VERSION 5.8 ;
BUSBITCHARS "[]" ;
DIVIDERCHAR "/" ;
UNITS
    DATABASE MICRONS 1000 ;
END UNITS

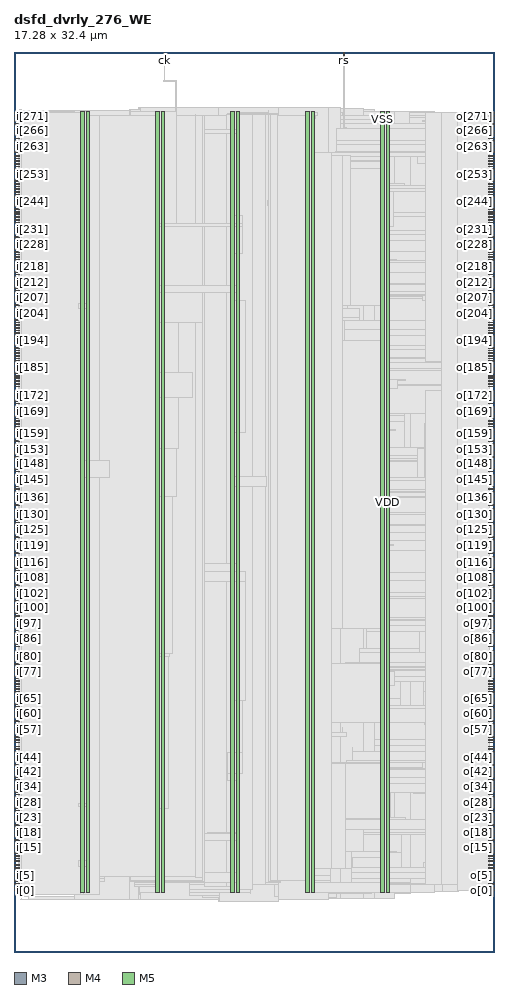
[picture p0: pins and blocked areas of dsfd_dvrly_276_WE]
MACRO dsfd_dvrly_276_WE
  FOREIGN dsfd_dvrly_276_WE 0 0 ;
  CLASS BLOCK ;
  SIZE 17.28 BY 32.4 ;
  PIN ck
    DIRECTION INPUT ;
    USE SIGNAL ;
    PORT
      LAYER M3 ;
        RECT  5.4 32.256 5.418 32.4 ;
    END
  END ck
  PIN i[0]
    DIRECTION INPUT ;
    USE SIGNAL ;
    PORT
      LAYER M4 ;
        RECT  0 2.208 0.192 2.232 ;
    END
  END i[0]
  PIN i[100]
    DIRECTION INPUT ;
    USE SIGNAL ;
    PORT
      LAYER M4 ;
        RECT  0 12.384 0.192 12.408 ;
    END
  END i[100]
  PIN i[101]
    DIRECTION INPUT ;
    USE SIGNAL ;
    PORT
      LAYER M4 ;
        RECT  0 12.48 0.192 12.504 ;
    END
  END i[101]
  PIN i[102]
    DIRECTION INPUT ;
    USE SIGNAL ;
    PORT
      LAYER M4 ;
        RECT  0 12.624 0.192 12.648 ;
    END
  END i[102]
  PIN i[103]
    DIRECTION INPUT ;
    USE SIGNAL ;
    PORT
      LAYER M4 ;
        RECT  0 12.72 0.192 12.744 ;
    END
  END i[103]
  PIN i[104]
    DIRECTION INPUT ;
    USE SIGNAL ;
    PORT
      LAYER M4 ;
        RECT  0 12.816 0.192 12.84 ;
    END
  END i[104]
  PIN i[105]
    DIRECTION INPUT ;
    USE SIGNAL ;
    PORT
      LAYER M4 ;
        RECT  0 12.912 0.192 12.936 ;
    END
  END i[105]
  PIN i[106]
    DIRECTION INPUT ;
    USE SIGNAL ;
    PORT
      LAYER M4 ;
        RECT  0 13.008 0.192 13.032 ;
    END
  END i[106]
  PIN i[107]
    DIRECTION INPUT ;
    USE SIGNAL ;
    PORT
      LAYER M4 ;
        RECT  0 13.104 0.192 13.128 ;
    END
  END i[107]
  PIN i[108]
    DIRECTION INPUT ;
    USE SIGNAL ;
    PORT
      LAYER M4 ;
        RECT  0 13.2 0.192 13.224 ;
    END
  END i[108]
  PIN i[109]
    DIRECTION INPUT ;
    USE SIGNAL ;
    PORT
      LAYER M4 ;
        RECT  0 13.296 0.192 13.32 ;
    END
  END i[109]
  PIN i[10]
    DIRECTION INPUT ;
    USE SIGNAL ;
    PORT
      LAYER M4 ;
        RECT  0 3.264 0.192 3.288 ;
    END
  END i[10]
  PIN i[110]
    DIRECTION INPUT ;
    USE SIGNAL ;
    PORT
      LAYER M4 ;
        RECT  0 13.392 0.192 13.416 ;
    END
  END i[110]
  PIN i[111]
    DIRECTION INPUT ;
    USE SIGNAL ;
    PORT
      LAYER M4 ;
        RECT  0 13.536 0.192 13.56 ;
    END
  END i[111]
  PIN i[112]
    DIRECTION INPUT ;
    USE SIGNAL ;
    PORT
      LAYER M4 ;
        RECT  0 13.632 0.192 13.656 ;
    END
  END i[112]
  PIN i[113]
    DIRECTION INPUT ;
    USE SIGNAL ;
    PORT
      LAYER M4 ;
        RECT  0 13.728 0.192 13.752 ;
    END
  END i[113]
  PIN i[114]
    DIRECTION INPUT ;
    USE SIGNAL ;
    PORT
      LAYER M4 ;
        RECT  0 13.824 0.192 13.848 ;
    END
  END i[114]
  PIN i[115]
    DIRECTION INPUT ;
    USE SIGNAL ;
    PORT
      LAYER M4 ;
        RECT  0 13.92 0.192 13.944 ;
    END
  END i[115]
  PIN i[116]
    DIRECTION INPUT ;
    USE SIGNAL ;
    PORT
      LAYER M4 ;
        RECT  0 14.016 0.192 14.04 ;
    END
  END i[116]
  PIN i[117]
    DIRECTION INPUT ;
    USE SIGNAL ;
    PORT
      LAYER M4 ;
        RECT  0 14.112 0.192 14.136 ;
    END
  END i[117]
  PIN i[118]
    DIRECTION INPUT ;
    USE SIGNAL ;
    PORT
      LAYER M4 ;
        RECT  0 14.208 0.192 14.232 ;
    END
  END i[118]
  PIN i[119]
    DIRECTION INPUT ;
    USE SIGNAL ;
    PORT
      LAYER M4 ;
        RECT  0 14.352 0.192 14.376 ;
    END
  END i[119]
  PIN i[11]
    DIRECTION INPUT ;
    USE SIGNAL ;
    PORT
      LAYER M4 ;
        RECT  0 3.36 0.192 3.384 ;
    END
  END i[11]
  PIN i[120]
    DIRECTION INPUT ;
    USE SIGNAL ;
    PORT
      LAYER M4 ;
        RECT  0 14.448 0.192 14.472 ;
    END
  END i[120]
  PIN i[121]
    DIRECTION INPUT ;
    USE SIGNAL ;
    PORT
      LAYER M4 ;
        RECT  0 14.544 0.192 14.568 ;
    END
  END i[121]
  PIN i[122]
    DIRECTION INPUT ;
    USE SIGNAL ;
    PORT
      LAYER M4 ;
        RECT  0 14.64 0.192 14.664 ;
    END
  END i[122]
  PIN i[123]
    DIRECTION INPUT ;
    USE SIGNAL ;
    PORT
      LAYER M4 ;
        RECT  0 14.736 0.192 14.76 ;
    END
  END i[123]
  PIN i[124]
    DIRECTION INPUT ;
    USE SIGNAL ;
    PORT
      LAYER M4 ;
        RECT  0 14.832 0.192 14.856 ;
    END
  END i[124]
  PIN i[125]
    DIRECTION INPUT ;
    USE SIGNAL ;
    PORT
      LAYER M4 ;
        RECT  0 14.928 0.192 14.952 ;
    END
  END i[125]
  PIN i[126]
    DIRECTION INPUT ;
    USE SIGNAL ;
    PORT
      LAYER M4 ;
        RECT  0 15.024 0.192 15.048 ;
    END
  END i[126]
  PIN i[127]
    DIRECTION INPUT ;
    USE SIGNAL ;
    PORT
      LAYER M4 ;
        RECT  0 15.12 0.192 15.144 ;
    END
  END i[127]
  PIN i[128]
    DIRECTION INPUT ;
    USE SIGNAL ;
    PORT
      LAYER M4 ;
        RECT  0 15.264 0.192 15.288 ;
    END
  END i[128]
  PIN i[129]
    DIRECTION INPUT ;
    USE SIGNAL ;
    PORT
      LAYER M4 ;
        RECT  0 15.36 0.192 15.384 ;
    END
  END i[129]
  PIN i[12]
    DIRECTION INPUT ;
    USE SIGNAL ;
    PORT
      LAYER M4 ;
        RECT  0 3.456 0.192 3.48 ;
    END
  END i[12]
  PIN i[130]
    DIRECTION INPUT ;
    USE SIGNAL ;
    PORT
      LAYER M4 ;
        RECT  0 15.456 0.192 15.48 ;
    END
  END i[130]
  PIN i[131]
    DIRECTION INPUT ;
    USE SIGNAL ;
    PORT
      LAYER M4 ;
        RECT  0 15.552 0.192 15.576 ;
    END
  END i[131]
  PIN i[132]
    DIRECTION INPUT ;
    USE SIGNAL ;
    PORT
      LAYER M4 ;
        RECT  0 15.648 0.192 15.672 ;
    END
  END i[132]
  PIN i[133]
    DIRECTION INPUT ;
    USE SIGNAL ;
    PORT
      LAYER M4 ;
        RECT  0 15.744 0.192 15.768 ;
    END
  END i[133]
  PIN i[134]
    DIRECTION INPUT ;
    USE SIGNAL ;
    PORT
      LAYER M4 ;
        RECT  0 15.84 0.192 15.864 ;
    END
  END i[134]
  PIN i[135]
    DIRECTION INPUT ;
    USE SIGNAL ;
    PORT
      LAYER M4 ;
        RECT  0 15.936 0.192 15.96 ;
    END
  END i[135]
  PIN i[136]
    DIRECTION INPUT ;
    USE SIGNAL ;
    PORT
      LAYER M4 ;
        RECT  0 16.08 0.192 16.104 ;
    END
  END i[136]
  PIN i[137]
    DIRECTION INPUT ;
    USE SIGNAL ;
    PORT
      LAYER M4 ;
        RECT  0 16.176 0.192 16.2 ;
    END
  END i[137]
  PIN i[138]
    DIRECTION INPUT ;
    USE SIGNAL ;
    PORT
      LAYER M4 ;
        RECT  0 16.272 0.192 16.296 ;
    END
  END i[138]
  PIN i[139]
    DIRECTION INPUT ;
    USE SIGNAL ;
    PORT
      LAYER M4 ;
        RECT  0 16.368 0.192 16.392 ;
    END
  END i[139]
  PIN i[13]
    DIRECTION INPUT ;
    USE SIGNAL ;
    PORT
      LAYER M4 ;
        RECT  0 3.552 0.192 3.576 ;
    END
  END i[13]
  PIN i[140]
    DIRECTION INPUT ;
    USE SIGNAL ;
    PORT
      LAYER M4 ;
        RECT  0 16.464 0.192 16.488 ;
    END
  END i[140]
  PIN i[141]
    DIRECTION INPUT ;
    USE SIGNAL ;
    PORT
      LAYER M4 ;
        RECT  0 16.56 0.192 16.584 ;
    END
  END i[141]
  PIN i[142]
    DIRECTION INPUT ;
    USE SIGNAL ;
    PORT
      LAYER M4 ;
        RECT  0 16.656 0.192 16.68 ;
    END
  END i[142]
  PIN i[143]
    DIRECTION INPUT ;
    USE SIGNAL ;
    PORT
      LAYER M4 ;
        RECT  0 16.752 0.192 16.776 ;
    END
  END i[143]
  PIN i[144]
    DIRECTION INPUT ;
    USE SIGNAL ;
    PORT
      LAYER M4 ;
        RECT  0 16.896 0.192 16.92 ;
    END
  END i[144]
  PIN i[145]
    DIRECTION INPUT ;
    USE SIGNAL ;
    PORT
      LAYER M4 ;
        RECT  0 16.992 0.192 17.016 ;
    END
  END i[145]
  PIN i[146]
    DIRECTION INPUT ;
    USE SIGNAL ;
    PORT
      LAYER M4 ;
        RECT  0 17.088 0.192 17.112 ;
    END
  END i[146]
  PIN i[147]
    DIRECTION INPUT ;
    USE SIGNAL ;
    PORT
      LAYER M4 ;
        RECT  0 17.184 0.192 17.208 ;
    END
  END i[147]
  PIN i[148]
    DIRECTION INPUT ;
    USE SIGNAL ;
    PORT
      LAYER M4 ;
        RECT  0 17.28 0.192 17.304 ;
    END
  END i[148]
  PIN i[149]
    DIRECTION INPUT ;
    USE SIGNAL ;
    PORT
      LAYER M4 ;
        RECT  0 17.376 0.192 17.4 ;
    END
  END i[149]
  PIN i[14]
    DIRECTION INPUT ;
    USE SIGNAL ;
    PORT
      LAYER M4 ;
        RECT  0 3.648 0.192 3.672 ;
    END
  END i[14]
  PIN i[150]
    DIRECTION INPUT ;
    USE SIGNAL ;
    PORT
      LAYER M4 ;
        RECT  0 17.472 0.192 17.496 ;
    END
  END i[150]
  PIN i[151]
    DIRECTION INPUT ;
    USE SIGNAL ;
    PORT
      LAYER M4 ;
        RECT  0 17.568 0.192 17.592 ;
    END
  END i[151]
  PIN i[152]
    DIRECTION INPUT ;
    USE SIGNAL ;
    PORT
      LAYER M4 ;
        RECT  0 17.664 0.192 17.688 ;
    END
  END i[152]
  PIN i[153]
    DIRECTION INPUT ;
    USE SIGNAL ;
    PORT
      LAYER M4 ;
        RECT  0 17.808 0.192 17.832 ;
    END
  END i[153]
  PIN i[154]
    DIRECTION INPUT ;
    USE SIGNAL ;
    PORT
      LAYER M4 ;
        RECT  0 17.904 0.192 17.928 ;
    END
  END i[154]
  PIN i[155]
    DIRECTION INPUT ;
    USE SIGNAL ;
    PORT
      LAYER M4 ;
        RECT  0 18 0.192 18.024 ;
    END
  END i[155]
  PIN i[156]
    DIRECTION INPUT ;
    USE SIGNAL ;
    PORT
      LAYER M4 ;
        RECT  0 18.096 0.192 18.12 ;
    END
  END i[156]
  PIN i[157]
    DIRECTION INPUT ;
    USE SIGNAL ;
    PORT
      LAYER M4 ;
        RECT  0 18.192 0.192 18.216 ;
    END
  END i[157]
  PIN i[158]
    DIRECTION INPUT ;
    USE SIGNAL ;
    PORT
      LAYER M4 ;
        RECT  0 18.288 0.192 18.312 ;
    END
  END i[158]
  PIN i[159]
    DIRECTION INPUT ;
    USE SIGNAL ;
    PORT
      LAYER M4 ;
        RECT  0 18.384 0.192 18.408 ;
    END
  END i[159]
  PIN i[15]
    DIRECTION INPUT ;
    USE SIGNAL ;
    PORT
      LAYER M4 ;
        RECT  0 3.744 0.192 3.768 ;
    END
  END i[15]
  PIN i[160]
    DIRECTION INPUT ;
    USE SIGNAL ;
    PORT
      LAYER M4 ;
        RECT  0 18.48 0.192 18.504 ;
    END
  END i[160]
  PIN i[161]
    DIRECTION INPUT ;
    USE SIGNAL ;
    PORT
      LAYER M4 ;
        RECT  0 18.624 0.192 18.648 ;
    END
  END i[161]
  PIN i[162]
    DIRECTION INPUT ;
    USE SIGNAL ;
    PORT
      LAYER M4 ;
        RECT  0 18.72 0.192 18.744 ;
    END
  END i[162]
  PIN i[163]
    DIRECTION INPUT ;
    USE SIGNAL ;
    PORT
      LAYER M4 ;
        RECT  0 18.816 0.192 18.84 ;
    END
  END i[163]
  PIN i[164]
    DIRECTION INPUT ;
    USE SIGNAL ;
    PORT
      LAYER M4 ;
        RECT  0 18.912 0.192 18.936 ;
    END
  END i[164]
  PIN i[165]
    DIRECTION INPUT ;
    USE SIGNAL ;
    PORT
      LAYER M4 ;
        RECT  0 19.008 0.192 19.032 ;
    END
  END i[165]
  PIN i[166]
    DIRECTION INPUT ;
    USE SIGNAL ;
    PORT
      LAYER M4 ;
        RECT  0 19.104 0.192 19.128 ;
    END
  END i[166]
  PIN i[167]
    DIRECTION INPUT ;
    USE SIGNAL ;
    PORT
      LAYER M4 ;
        RECT  0 19.2 0.192 19.224 ;
    END
  END i[167]
  PIN i[168]
    DIRECTION INPUT ;
    USE SIGNAL ;
    PORT
      LAYER M4 ;
        RECT  0 19.296 0.192 19.32 ;
    END
  END i[168]
  PIN i[169]
    DIRECTION INPUT ;
    USE SIGNAL ;
    PORT
      LAYER M4 ;
        RECT  0 19.44 0.192 19.464 ;
    END
  END i[169]
  PIN i[16]
    DIRECTION INPUT ;
    USE SIGNAL ;
    PORT
      LAYER M4 ;
        RECT  0 3.84 0.192 3.864 ;
    END
  END i[16]
  PIN i[170]
    DIRECTION INPUT ;
    USE SIGNAL ;
    PORT
      LAYER M4 ;
        RECT  0 19.536 0.192 19.56 ;
    END
  END i[170]
  PIN i[171]
    DIRECTION INPUT ;
    USE SIGNAL ;
    PORT
      LAYER M4 ;
        RECT  0 19.632 0.192 19.656 ;
    END
  END i[171]
  PIN i[172]
    DIRECTION INPUT ;
    USE SIGNAL ;
    PORT
      LAYER M4 ;
        RECT  0 19.728 0.192 19.752 ;
    END
  END i[172]
  PIN i[173]
    DIRECTION INPUT ;
    USE SIGNAL ;
    PORT
      LAYER M4 ;
        RECT  0 19.824 0.192 19.848 ;
    END
  END i[173]
  PIN i[174]
    DIRECTION INPUT ;
    USE SIGNAL ;
    PORT
      LAYER M4 ;
        RECT  0 19.92 0.192 19.944 ;
    END
  END i[174]
  PIN i[175]
    DIRECTION INPUT ;
    USE SIGNAL ;
    PORT
      LAYER M4 ;
        RECT  0 20.016 0.192 20.04 ;
    END
  END i[175]
  PIN i[176]
    DIRECTION INPUT ;
    USE SIGNAL ;
    PORT
      LAYER M4 ;
        RECT  0 20.112 0.192 20.136 ;
    END
  END i[176]
  PIN i[177]
    DIRECTION INPUT ;
    USE SIGNAL ;
    PORT
      LAYER M4 ;
        RECT  0 20.208 0.192 20.232 ;
    END
  END i[177]
  PIN i[178]
    DIRECTION INPUT ;
    USE SIGNAL ;
    PORT
      LAYER M4 ;
        RECT  0 20.352 0.192 20.376 ;
    END
  END i[178]
  PIN i[179]
    DIRECTION INPUT ;
    USE SIGNAL ;
    PORT
      LAYER M4 ;
        RECT  0 20.448 0.192 20.472 ;
    END
  END i[179]
  PIN i[17]
    DIRECTION INPUT ;
    USE SIGNAL ;
    PORT
      LAYER M4 ;
        RECT  0 3.936 0.192 3.96 ;
    END
  END i[17]
  PIN i[180]
    DIRECTION INPUT ;
    USE SIGNAL ;
    PORT
      LAYER M4 ;
        RECT  0 20.544 0.192 20.568 ;
    END
  END i[180]
  PIN i[181]
    DIRECTION INPUT ;
    USE SIGNAL ;
    PORT
      LAYER M4 ;
        RECT  0 20.64 0.192 20.664 ;
    END
  END i[181]
  PIN i[182]
    DIRECTION INPUT ;
    USE SIGNAL ;
    PORT
      LAYER M4 ;
        RECT  0 20.736 0.192 20.76 ;
    END
  END i[182]
  PIN i[183]
    DIRECTION INPUT ;
    USE SIGNAL ;
    PORT
      LAYER M4 ;
        RECT  0 20.832 0.192 20.856 ;
    END
  END i[183]
  PIN i[184]
    DIRECTION INPUT ;
    USE SIGNAL ;
    PORT
      LAYER M4 ;
        RECT  0 20.928 0.192 20.952 ;
    END
  END i[184]
  PIN i[185]
    DIRECTION INPUT ;
    USE SIGNAL ;
    PORT
      LAYER M4 ;
        RECT  0 21.024 0.192 21.048 ;
    END
  END i[185]
  PIN i[186]
    DIRECTION INPUT ;
    USE SIGNAL ;
    PORT
      LAYER M4 ;
        RECT  0 21.168 0.192 21.192 ;
    END
  END i[186]
  PIN i[187]
    DIRECTION INPUT ;
    USE SIGNAL ;
    PORT
      LAYER M4 ;
        RECT  0 21.264 0.192 21.288 ;
    END
  END i[187]
  PIN i[188]
    DIRECTION INPUT ;
    USE SIGNAL ;
    PORT
      LAYER M4 ;
        RECT  0 21.36 0.192 21.384 ;
    END
  END i[188]
  PIN i[189]
    DIRECTION INPUT ;
    USE SIGNAL ;
    PORT
      LAYER M4 ;
        RECT  0 21.456 0.192 21.48 ;
    END
  END i[189]
  PIN i[18]
    DIRECTION INPUT ;
    USE SIGNAL ;
    PORT
      LAYER M4 ;
        RECT  0 4.032 0.192 4.056 ;
    END
  END i[18]
  PIN i[190]
    DIRECTION INPUT ;
    USE SIGNAL ;
    PORT
      LAYER M4 ;
        RECT  0 21.552 0.192 21.576 ;
    END
  END i[190]
  PIN i[191]
    DIRECTION INPUT ;
    USE SIGNAL ;
    PORT
      LAYER M4 ;
        RECT  0 21.648 0.192 21.672 ;
    END
  END i[191]
  PIN i[192]
    DIRECTION INPUT ;
    USE SIGNAL ;
    PORT
      LAYER M4 ;
        RECT  0 21.744 0.192 21.768 ;
    END
  END i[192]
  PIN i[193]
    DIRECTION INPUT ;
    USE SIGNAL ;
    PORT
      LAYER M4 ;
        RECT  0 21.84 0.192 21.864 ;
    END
  END i[193]
  PIN i[194]
    DIRECTION INPUT ;
    USE SIGNAL ;
    PORT
      LAYER M4 ;
        RECT  0 21.984 0.192 22.008 ;
    END
  END i[194]
  PIN i[195]
    DIRECTION INPUT ;
    USE SIGNAL ;
    PORT
      LAYER M4 ;
        RECT  0 22.08 0.192 22.104 ;
    END
  END i[195]
  PIN i[196]
    DIRECTION INPUT ;
    USE SIGNAL ;
    PORT
      LAYER M4 ;
        RECT  0 22.176 0.192 22.2 ;
    END
  END i[196]
  PIN i[197]
    DIRECTION INPUT ;
    USE SIGNAL ;
    PORT
      LAYER M4 ;
        RECT  0 22.272 0.192 22.296 ;
    END
  END i[197]
  PIN i[198]
    DIRECTION INPUT ;
    USE SIGNAL ;
    PORT
      LAYER M4 ;
        RECT  0 22.368 0.192 22.392 ;
    END
  END i[198]
  PIN i[199]
    DIRECTION INPUT ;
    USE SIGNAL ;
    PORT
      LAYER M4 ;
        RECT  0 22.464 0.192 22.488 ;
    END
  END i[199]
  PIN i[19]
    DIRECTION INPUT ;
    USE SIGNAL ;
    PORT
      LAYER M4 ;
        RECT  0 4.176 0.192 4.2 ;
    END
  END i[19]
  PIN i[1]
    DIRECTION INPUT ;
    USE SIGNAL ;
    PORT
      LAYER M4 ;
        RECT  0 2.304 0.192 2.328 ;
    END
  END i[1]
  PIN i[200]
    DIRECTION INPUT ;
    USE SIGNAL ;
    PORT
      LAYER M4 ;
        RECT  0 22.56 0.192 22.584 ;
    END
  END i[200]
  PIN i[201]
    DIRECTION INPUT ;
    USE SIGNAL ;
    PORT
      LAYER M4 ;
        RECT  0 22.656 0.192 22.68 ;
    END
  END i[201]
  PIN i[202]
    DIRECTION INPUT ;
    USE SIGNAL ;
    PORT
      LAYER M4 ;
        RECT  0 22.752 0.192 22.776 ;
    END
  END i[202]
  PIN i[203]
    DIRECTION INPUT ;
    USE SIGNAL ;
    PORT
      LAYER M4 ;
        RECT  0 22.896 0.192 22.92 ;
    END
  END i[203]
  PIN i[204]
    DIRECTION INPUT ;
    USE SIGNAL ;
    PORT
      LAYER M4 ;
        RECT  0 22.992 0.192 23.016 ;
    END
  END i[204]
  PIN i[205]
    DIRECTION INPUT ;
    USE SIGNAL ;
    PORT
      LAYER M4 ;
        RECT  0 23.088 0.192 23.112 ;
    END
  END i[205]
  PIN i[206]
    DIRECTION INPUT ;
    USE SIGNAL ;
    PORT
      LAYER M4 ;
        RECT  0 23.184 0.192 23.208 ;
    END
  END i[206]
  PIN i[207]
    DIRECTION INPUT ;
    USE SIGNAL ;
    PORT
      LAYER M4 ;
        RECT  0 23.28 0.192 23.304 ;
    END
  END i[207]
  PIN i[208]
    DIRECTION INPUT ;
    USE SIGNAL ;
    PORT
      LAYER M4 ;
        RECT  0 23.376 0.192 23.4 ;
    END
  END i[208]
  PIN i[209]
    DIRECTION INPUT ;
    USE SIGNAL ;
    PORT
      LAYER M4 ;
        RECT  0 23.472 0.192 23.496 ;
    END
  END i[209]
  PIN i[20]
    DIRECTION INPUT ;
    USE SIGNAL ;
    PORT
      LAYER M4 ;
        RECT  0 4.272 0.192 4.296 ;
    END
  END i[20]
  PIN i[210]
    DIRECTION INPUT ;
    USE SIGNAL ;
    PORT
      LAYER M4 ;
        RECT  0 23.568 0.192 23.592 ;
    END
  END i[210]
  PIN i[211]
    DIRECTION INPUT ;
    USE SIGNAL ;
    PORT
      LAYER M4 ;
        RECT  0 23.712 0.192 23.736 ;
    END
  END i[211]
  PIN i[212]
    DIRECTION INPUT ;
    USE SIGNAL ;
    PORT
      LAYER M4 ;
        RECT  0 23.808 0.192 23.832 ;
    END
  END i[212]
  PIN i[213]
    DIRECTION INPUT ;
    USE SIGNAL ;
    PORT
      LAYER M4 ;
        RECT  0 23.904 0.192 23.928 ;
    END
  END i[213]
  PIN i[214]
    DIRECTION INPUT ;
    USE SIGNAL ;
    PORT
      LAYER M4 ;
        RECT  0 24 0.192 24.024 ;
    END
  END i[214]
  PIN i[215]
    DIRECTION INPUT ;
    USE SIGNAL ;
    PORT
      LAYER M4 ;
        RECT  0 24.096 0.192 24.12 ;
    END
  END i[215]
  PIN i[216]
    DIRECTION INPUT ;
    USE SIGNAL ;
    PORT
      LAYER M4 ;
        RECT  0 24.192 0.192 24.216 ;
    END
  END i[216]
  PIN i[217]
    DIRECTION INPUT ;
    USE SIGNAL ;
    PORT
      LAYER M4 ;
        RECT  0 24.288 0.192 24.312 ;
    END
  END i[217]
  PIN i[218]
    DIRECTION INPUT ;
    USE SIGNAL ;
    PORT
      LAYER M4 ;
        RECT  0 24.384 0.192 24.408 ;
    END
  END i[218]
  PIN i[219]
    DIRECTION INPUT ;
    USE SIGNAL ;
    PORT
      LAYER M4 ;
        RECT  0 24.48 0.192 24.504 ;
    END
  END i[219]
  PIN i[21]
    DIRECTION INPUT ;
    USE SIGNAL ;
    PORT
      LAYER M4 ;
        RECT  0 4.368 0.192 4.392 ;
    END
  END i[21]
  PIN i[220]
    DIRECTION INPUT ;
    USE SIGNAL ;
    PORT
      LAYER M4 ;
        RECT  0 24.624 0.192 24.648 ;
    END
  END i[220]
  PIN i[221]
    DIRECTION INPUT ;
    USE SIGNAL ;
    PORT
      LAYER M4 ;
        RECT  0 24.72 0.192 24.744 ;
    END
  END i[221]
  PIN i[222]
    DIRECTION INPUT ;
    USE SIGNAL ;
    PORT
      LAYER M4 ;
        RECT  0 24.816 0.192 24.84 ;
    END
  END i[222]
  PIN i[223]
    DIRECTION INPUT ;
    USE SIGNAL ;
    PORT
      LAYER M4 ;
        RECT  0 24.912 0.192 24.936 ;
    END
  END i[223]
  PIN i[224]
    DIRECTION INPUT ;
    USE SIGNAL ;
    PORT
      LAYER M4 ;
        RECT  0 25.008 0.192 25.032 ;
    END
  END i[224]
  PIN i[225]
    DIRECTION INPUT ;
    USE SIGNAL ;
    PORT
      LAYER M4 ;
        RECT  0 25.104 0.192 25.128 ;
    END
  END i[225]
  PIN i[226]
    DIRECTION INPUT ;
    USE SIGNAL ;
    PORT
      LAYER M4 ;
        RECT  0 25.2 0.192 25.224 ;
    END
  END i[226]
  PIN i[227]
    DIRECTION INPUT ;
    USE SIGNAL ;
    PORT
      LAYER M4 ;
        RECT  0 25.296 0.192 25.32 ;
    END
  END i[227]
  PIN i[228]
    DIRECTION INPUT ;
    USE SIGNAL ;
    PORT
      LAYER M4 ;
        RECT  0 25.44 0.192 25.464 ;
    END
  END i[228]
  PIN i[229]
    DIRECTION INPUT ;
    USE SIGNAL ;
    PORT
      LAYER M4 ;
        RECT  0 25.536 0.192 25.56 ;
    END
  END i[229]
  PIN i[22]
    DIRECTION INPUT ;
    USE SIGNAL ;
    PORT
      LAYER M4 ;
        RECT  0 4.464 0.192 4.488 ;
    END
  END i[22]
  PIN i[230]
    DIRECTION INPUT ;
    USE SIGNAL ;
    PORT
      LAYER M4 ;
        RECT  0 25.632 0.192 25.656 ;
    END
  END i[230]
  PIN i[231]
    DIRECTION INPUT ;
    USE SIGNAL ;
    PORT
      LAYER M4 ;
        RECT  0 25.728 0.192 25.752 ;
    END
  END i[231]
  PIN i[232]
    DIRECTION INPUT ;
    USE SIGNAL ;
    PORT
      LAYER M4 ;
        RECT  0 25.824 0.192 25.848 ;
    END
  END i[232]
  PIN i[233]
    DIRECTION INPUT ;
    USE SIGNAL ;
    PORT
      LAYER M4 ;
        RECT  0 25.92 0.192 25.944 ;
    END
  END i[233]
  PIN i[234]
    DIRECTION INPUT ;
    USE SIGNAL ;
    PORT
      LAYER M4 ;
        RECT  0 26.016 0.192 26.04 ;
    END
  END i[234]
  PIN i[235]
    DIRECTION INPUT ;
    USE SIGNAL ;
    PORT
      LAYER M4 ;
        RECT  0 26.112 0.192 26.136 ;
    END
  END i[235]
  PIN i[236]
    DIRECTION INPUT ;
    USE SIGNAL ;
    PORT
      LAYER M4 ;
        RECT  0 26.256 0.192 26.28 ;
    END
  END i[236]
  PIN i[237]
    DIRECTION INPUT ;
    USE SIGNAL ;
    PORT
      LAYER M4 ;
        RECT  0 26.352 0.192 26.376 ;
    END
  END i[237]
  PIN i[238]
    DIRECTION INPUT ;
    USE SIGNAL ;
    PORT
      LAYER M4 ;
        RECT  0 26.448 0.192 26.472 ;
    END
  END i[238]
  PIN i[239]
    DIRECTION INPUT ;
    USE SIGNAL ;
    PORT
      LAYER M4 ;
        RECT  0 26.544 0.192 26.568 ;
    END
  END i[239]
  PIN i[23]
    DIRECTION INPUT ;
    USE SIGNAL ;
    PORT
      LAYER M4 ;
        RECT  0 4.56 0.192 4.584 ;
    END
  END i[23]
  PIN i[240]
    DIRECTION INPUT ;
    USE SIGNAL ;
    PORT
      LAYER M4 ;
        RECT  0 26.64 0.192 26.664 ;
    END
  END i[240]
  PIN i[241]
    DIRECTION INPUT ;
    USE SIGNAL ;
    PORT
      LAYER M4 ;
        RECT  0 26.736 0.192 26.76 ;
    END
  END i[241]
  PIN i[242]
    DIRECTION INPUT ;
    USE SIGNAL ;
    PORT
      LAYER M4 ;
        RECT  0 26.832 0.192 26.856 ;
    END
  END i[242]
  PIN i[243]
    DIRECTION INPUT ;
    USE SIGNAL ;
    PORT
      LAYER M4 ;
        RECT  0 26.928 0.192 26.952 ;
    END
  END i[243]
  PIN i[244]
    DIRECTION INPUT ;
    USE SIGNAL ;
    PORT
      LAYER M4 ;
        RECT  0 27.024 0.192 27.048 ;
    END
  END i[244]
  PIN i[245]
    DIRECTION INPUT ;
    USE SIGNAL ;
    PORT
      LAYER M4 ;
        RECT  0 27.168 0.192 27.192 ;
    END
  END i[245]
  PIN i[246]
    DIRECTION INPUT ;
    USE SIGNAL ;
    PORT
      LAYER M4 ;
        RECT  0 27.264 0.192 27.288 ;
    END
  END i[246]
  PIN i[247]
    DIRECTION INPUT ;
    USE SIGNAL ;
    PORT
      LAYER M4 ;
        RECT  0 27.36 0.192 27.384 ;
    END
  END i[247]
  PIN i[248]
    DIRECTION INPUT ;
    USE SIGNAL ;
    PORT
      LAYER M4 ;
        RECT  0 27.456 0.192 27.48 ;
    END
  END i[248]
  PIN i[249]
    DIRECTION INPUT ;
    USE SIGNAL ;
    PORT
      LAYER M4 ;
        RECT  0 27.552 0.192 27.576 ;
    END
  END i[249]
  PIN i[24]
    DIRECTION INPUT ;
    USE SIGNAL ;
    PORT
      LAYER M4 ;
        RECT  0 4.656 0.192 4.68 ;
    END
  END i[24]
  PIN i[250]
    DIRECTION INPUT ;
    USE SIGNAL ;
    PORT
      LAYER M4 ;
        RECT  0 27.648 0.192 27.672 ;
    END
  END i[250]
  PIN i[251]
    DIRECTION INPUT ;
    USE SIGNAL ;
    PORT
      LAYER M4 ;
        RECT  0 27.744 0.192 27.768 ;
    END
  END i[251]
  PIN i[252]
    DIRECTION INPUT ;
    USE SIGNAL ;
    PORT
      LAYER M4 ;
        RECT  0 27.84 0.192 27.864 ;
    END
  END i[252]
  PIN i[253]
    DIRECTION INPUT ;
    USE SIGNAL ;
    PORT
      LAYER M4 ;
        RECT  0 27.984 0.192 28.008 ;
    END
  END i[253]
  PIN i[254]
    DIRECTION INPUT ;
    USE SIGNAL ;
    PORT
      LAYER M4 ;
        RECT  0 28.08 0.192 28.104 ;
    END
  END i[254]
  PIN i[255]
    DIRECTION INPUT ;
    USE SIGNAL ;
    PORT
      LAYER M4 ;
        RECT  0 28.176 0.192 28.2 ;
    END
  END i[255]
  PIN i[256]
    DIRECTION INPUT ;
    USE SIGNAL ;
    PORT
      LAYER M4 ;
        RECT  0 28.272 0.192 28.296 ;
    END
  END i[256]
  PIN i[257]
    DIRECTION INPUT ;
    USE SIGNAL ;
    PORT
      LAYER M4 ;
        RECT  0 28.368 0.192 28.392 ;
    END
  END i[257]
  PIN i[258]
    DIRECTION INPUT ;
    USE SIGNAL ;
    PORT
      LAYER M4 ;
        RECT  0 28.464 0.192 28.488 ;
    END
  END i[258]
  PIN i[259]
    DIRECTION INPUT ;
    USE SIGNAL ;
    PORT
      LAYER M4 ;
        RECT  0 28.56 0.192 28.584 ;
    END
  END i[259]
  PIN i[25]
    DIRECTION INPUT ;
    USE SIGNAL ;
    PORT
      LAYER M4 ;
        RECT  0 4.752 0.192 4.776 ;
    END
  END i[25]
  PIN i[260]
    DIRECTION INPUT ;
    USE SIGNAL ;
    PORT
      LAYER M4 ;
        RECT  0 28.656 0.192 28.68 ;
    END
  END i[260]
  PIN i[261]
    DIRECTION INPUT ;
    USE SIGNAL ;
    PORT
      LAYER M4 ;
        RECT  0 28.8 0.192 28.824 ;
    END
  END i[261]
  PIN i[262]
    DIRECTION INPUT ;
    USE SIGNAL ;
    PORT
      LAYER M4 ;
        RECT  0 28.896 0.192 28.92 ;
    END
  END i[262]
  PIN i[263]
    DIRECTION INPUT ;
    USE SIGNAL ;
    PORT
      LAYER M4 ;
        RECT  0 28.992 0.192 29.016 ;
    END
  END i[263]
  PIN i[264]
    DIRECTION INPUT ;
    USE SIGNAL ;
    PORT
      LAYER M4 ;
        RECT  0 29.088 0.192 29.112 ;
    END
  END i[264]
  PIN i[265]
    DIRECTION INPUT ;
    USE SIGNAL ;
    PORT
      LAYER M4 ;
        RECT  0 29.184 0.192 29.208 ;
    END
  END i[265]
  PIN i[266]
    DIRECTION INPUT ;
    USE SIGNAL ;
    PORT
      LAYER M4 ;
        RECT  0 29.28 0.192 29.304 ;
    END
  END i[266]
  PIN i[267]
    DIRECTION INPUT ;
    USE SIGNAL ;
    PORT
      LAYER M4 ;
        RECT  0 29.376 0.192 29.4 ;
    END
  END i[267]
  PIN i[268]
    DIRECTION INPUT ;
    USE SIGNAL ;
    PORT
      LAYER M4 ;
        RECT  0 29.472 0.192 29.496 ;
    END
  END i[268]
  PIN i[269]
    DIRECTION INPUT ;
    USE SIGNAL ;
    PORT
      LAYER M4 ;
        RECT  0 29.568 0.192 29.592 ;
    END
  END i[269]
  PIN i[26]
    DIRECTION INPUT ;
    USE SIGNAL ;
    PORT
      LAYER M4 ;
        RECT  0 4.848 0.192 4.872 ;
    END
  END i[26]
  PIN i[270]
    DIRECTION INPUT ;
    USE SIGNAL ;
    PORT
      LAYER M4 ;
        RECT  0 29.712 0.192 29.736 ;
    END
  END i[270]
  PIN i[271]
    DIRECTION INPUT ;
    USE SIGNAL ;
    PORT
      LAYER M4 ;
        RECT  0 29.808 0.192 29.832 ;
    END
  END i[271]
  PIN i[272]
    DIRECTION INPUT ;
    USE SIGNAL ;
    PORT
      LAYER M4 ;
        RECT  0 29.904 0.192 29.928 ;
    END
  END i[272]
  PIN i[273]
    DIRECTION INPUT ;
    USE SIGNAL ;
    PORT
      LAYER M4 ;
        RECT  0 30 0.192 30.024 ;
    END
  END i[273]
  PIN i[274]
    DIRECTION INPUT ;
    USE SIGNAL ;
    PORT
      LAYER M4 ;
        RECT  0 30.096 0.192 30.12 ;
    END
  END i[274]
  PIN i[275]
    DIRECTION INPUT ;
    USE SIGNAL ;
    PORT
      LAYER M4 ;
        RECT  0 30.192 0.192 30.216 ;
    END
  END i[275]
  PIN i[27]
    DIRECTION INPUT ;
    USE SIGNAL ;
    PORT
      LAYER M4 ;
        RECT  0 4.992 0.192 5.016 ;
    END
  END i[27]
  PIN i[28]
    DIRECTION INPUT ;
    USE SIGNAL ;
    PORT
      LAYER M4 ;
        RECT  0 5.088 0.192 5.112 ;
    END
  END i[28]
  PIN i[29]
    DIRECTION INPUT ;
    USE SIGNAL ;
    PORT
      LAYER M4 ;
        RECT  0 5.184 0.192 5.208 ;
    END
  END i[29]
  PIN i[2]
    DIRECTION INPUT ;
    USE SIGNAL ;
    PORT
      LAYER M4 ;
        RECT  0 2.448 0.192 2.472 ;
    END
  END i[2]
  PIN i[30]
    DIRECTION INPUT ;
    USE SIGNAL ;
    PORT
      LAYER M4 ;
        RECT  0 5.28 0.192 5.304 ;
    END
  END i[30]
  PIN i[31]
    DIRECTION INPUT ;
    USE SIGNAL ;
    PORT
      LAYER M4 ;
        RECT  0 5.376 0.192 5.4 ;
    END
  END i[31]
  PIN i[32]
    DIRECTION INPUT ;
    USE SIGNAL ;
    PORT
      LAYER M4 ;
        RECT  0 5.472 0.192 5.496 ;
    END
  END i[32]
  PIN i[33]
    DIRECTION INPUT ;
    USE SIGNAL ;
    PORT
      LAYER M4 ;
        RECT  0 5.568 0.192 5.592 ;
    END
  END i[33]
  PIN i[34]
    DIRECTION INPUT ;
    USE SIGNAL ;
    PORT
      LAYER M4 ;
        RECT  0 5.664 0.192 5.688 ;
    END
  END i[34]
  PIN i[35]
    DIRECTION INPUT ;
    USE SIGNAL ;
    PORT
      LAYER M4 ;
        RECT  0 5.76 0.192 5.784 ;
    END
  END i[35]
  PIN i[36]
    DIRECTION INPUT ;
    USE SIGNAL ;
    PORT
      LAYER M4 ;
        RECT  0 5.904 0.192 5.928 ;
    END
  END i[36]
  PIN i[37]
    DIRECTION INPUT ;
    USE SIGNAL ;
    PORT
      LAYER M4 ;
        RECT  0 6 0.192 6.024 ;
    END
  END i[37]
  PIN i[38]
    DIRECTION INPUT ;
    USE SIGNAL ;
    PORT
      LAYER M4 ;
        RECT  0 6.096 0.192 6.12 ;
    END
  END i[38]
  PIN i[39]
    DIRECTION INPUT ;
    USE SIGNAL ;
    PORT
      LAYER M4 ;
        RECT  0 6.192 0.192 6.216 ;
    END
  END i[39]
  PIN i[3]
    DIRECTION INPUT ;
    USE SIGNAL ;
    PORT
      LAYER M4 ;
        RECT  0 2.544 0.192 2.568 ;
    END
  END i[3]
  PIN i[40]
    DIRECTION INPUT ;
    USE SIGNAL ;
    PORT
      LAYER M4 ;
        RECT  0 6.288 0.192 6.312 ;
    END
  END i[40]
  PIN i[41]
    DIRECTION INPUT ;
    USE SIGNAL ;
    PORT
      LAYER M4 ;
        RECT  0 6.384 0.192 6.408 ;
    END
  END i[41]
  PIN i[42]
    DIRECTION INPUT ;
    USE SIGNAL ;
    PORT
      LAYER M4 ;
        RECT  0 6.48 0.192 6.504 ;
    END
  END i[42]
  PIN i[43]
    DIRECTION INPUT ;
    USE SIGNAL ;
    PORT
      LAYER M4 ;
        RECT  0 6.576 0.192 6.6 ;
    END
  END i[43]
  PIN i[44]
    DIRECTION INPUT ;
    USE SIGNAL ;
    PORT
      LAYER M4 ;
        RECT  0 6.72 0.192 6.744 ;
    END
  END i[44]
  PIN i[45]
    DIRECTION INPUT ;
    USE SIGNAL ;
    PORT
      LAYER M4 ;
        RECT  0 6.816 0.192 6.84 ;
    END
  END i[45]
  PIN i[46]
    DIRECTION INPUT ;
    USE SIGNAL ;
    PORT
      LAYER M4 ;
        RECT  0 6.912 0.192 6.936 ;
    END
  END i[46]
  PIN i[47]
    DIRECTION INPUT ;
    USE SIGNAL ;
    PORT
      LAYER M4 ;
        RECT  0 7.008 0.192 7.032 ;
    END
  END i[47]
  PIN i[48]
    DIRECTION INPUT ;
    USE SIGNAL ;
    PORT
      LAYER M4 ;
        RECT  0 7.104 0.192 7.128 ;
    END
  END i[48]
  PIN i[49]
    DIRECTION INPUT ;
    USE SIGNAL ;
    PORT
      LAYER M4 ;
        RECT  0 7.2 0.192 7.224 ;
    END
  END i[49]
  PIN i[4]
    DIRECTION INPUT ;
    USE SIGNAL ;
    PORT
      LAYER M4 ;
        RECT  0 2.64 0.192 2.664 ;
    END
  END i[4]
  PIN i[50]
    DIRECTION INPUT ;
    USE SIGNAL ;
    PORT
      LAYER M4 ;
        RECT  0 7.296 0.192 7.32 ;
    END
  END i[50]
  PIN i[51]
    DIRECTION INPUT ;
    USE SIGNAL ;
    PORT
      LAYER M4 ;
        RECT  0 7.392 0.192 7.416 ;
    END
  END i[51]
  PIN i[52]
    DIRECTION INPUT ;
    USE SIGNAL ;
    PORT
      LAYER M4 ;
        RECT  0 7.536 0.192 7.56 ;
    END
  END i[52]
  PIN i[53]
    DIRECTION INPUT ;
    USE SIGNAL ;
    PORT
      LAYER M4 ;
        RECT  0 7.632 0.192 7.656 ;
    END
  END i[53]
  PIN i[54]
    DIRECTION INPUT ;
    USE SIGNAL ;
    PORT
      LAYER M4 ;
        RECT  0 7.728 0.192 7.752 ;
    END
  END i[54]
  PIN i[55]
    DIRECTION INPUT ;
    USE SIGNAL ;
    PORT
      LAYER M4 ;
        RECT  0 7.824 0.192 7.848 ;
    END
  END i[55]
  PIN i[56]
    DIRECTION INPUT ;
    USE SIGNAL ;
    PORT
      LAYER M4 ;
        RECT  0 7.92 0.192 7.944 ;
    END
  END i[56]
  PIN i[57]
    DIRECTION INPUT ;
    USE SIGNAL ;
    PORT
      LAYER M4 ;
        RECT  0 8.016 0.192 8.04 ;
    END
  END i[57]
  PIN i[58]
    DIRECTION INPUT ;
    USE SIGNAL ;
    PORT
      LAYER M4 ;
        RECT  0 8.112 0.192 8.136 ;
    END
  END i[58]
  PIN i[59]
    DIRECTION INPUT ;
    USE SIGNAL ;
    PORT
      LAYER M4 ;
        RECT  0 8.208 0.192 8.232 ;
    END
  END i[59]
  PIN i[5]
    DIRECTION INPUT ;
    USE SIGNAL ;
    PORT
      LAYER M4 ;
        RECT  0 2.736 0.192 2.76 ;
    END
  END i[5]
  PIN i[60]
    DIRECTION INPUT ;
    USE SIGNAL ;
    PORT
      LAYER M4 ;
        RECT  0 8.304 0.192 8.328 ;
    END
  END i[60]
  PIN i[61]
    DIRECTION INPUT ;
    USE SIGNAL ;
    PORT
      LAYER M4 ;
        RECT  0 8.448 0.192 8.472 ;
    END
  END i[61]
  PIN i[62]
    DIRECTION INPUT ;
    USE SIGNAL ;
    PORT
      LAYER M4 ;
        RECT  0 8.544 0.192 8.568 ;
    END
  END i[62]
  PIN i[63]
    DIRECTION INPUT ;
    USE SIGNAL ;
    PORT
      LAYER M4 ;
        RECT  0 8.64 0.192 8.664 ;
    END
  END i[63]
  PIN i[64]
    DIRECTION INPUT ;
    USE SIGNAL ;
    PORT
      LAYER M4 ;
        RECT  0 8.736 0.192 8.76 ;
    END
  END i[64]
  PIN i[65]
    DIRECTION INPUT ;
    USE SIGNAL ;
    PORT
      LAYER M4 ;
        RECT  0 8.832 0.192 8.856 ;
    END
  END i[65]
  PIN i[66]
    DIRECTION INPUT ;
    USE SIGNAL ;
    PORT
      LAYER M4 ;
        RECT  0 8.928 0.192 8.952 ;
    END
  END i[66]
  PIN i[67]
    DIRECTION INPUT ;
    USE SIGNAL ;
    PORT
      LAYER M4 ;
        RECT  0 9.024 0.192 9.048 ;
    END
  END i[67]
  PIN i[68]
    DIRECTION INPUT ;
    USE SIGNAL ;
    PORT
      LAYER M4 ;
        RECT  0 9.12 0.192 9.144 ;
    END
  END i[68]
  PIN i[69]
    DIRECTION INPUT ;
    USE SIGNAL ;
    PORT
      LAYER M4 ;
        RECT  0 9.264 0.192 9.288 ;
    END
  END i[69]
  PIN i[6]
    DIRECTION INPUT ;
    USE SIGNAL ;
    PORT
      LAYER M4 ;
        RECT  0 2.832 0.192 2.856 ;
    END
  END i[6]
  PIN i[70]
    DIRECTION INPUT ;
    USE SIGNAL ;
    PORT
      LAYER M4 ;
        RECT  0 9.36 0.192 9.384 ;
    END
  END i[70]
  PIN i[71]
    DIRECTION INPUT ;
    USE SIGNAL ;
    PORT
      LAYER M4 ;
        RECT  0 9.456 0.192 9.48 ;
    END
  END i[71]
  PIN i[72]
    DIRECTION INPUT ;
    USE SIGNAL ;
    PORT
      LAYER M4 ;
        RECT  0 9.552 0.192 9.576 ;
    END
  END i[72]
  PIN i[73]
    DIRECTION INPUT ;
    USE SIGNAL ;
    PORT
      LAYER M4 ;
        RECT  0 9.648 0.192 9.672 ;
    END
  END i[73]
  PIN i[74]
    DIRECTION INPUT ;
    USE SIGNAL ;
    PORT
      LAYER M4 ;
        RECT  0 9.744 0.192 9.768 ;
    END
  END i[74]
  PIN i[75]
    DIRECTION INPUT ;
    USE SIGNAL ;
    PORT
      LAYER M4 ;
        RECT  0 9.84 0.192 9.864 ;
    END
  END i[75]
  PIN i[76]
    DIRECTION INPUT ;
    USE SIGNAL ;
    PORT
      LAYER M4 ;
        RECT  0 9.936 0.192 9.96 ;
    END
  END i[76]
  PIN i[77]
    DIRECTION INPUT ;
    USE SIGNAL ;
    PORT
      LAYER M4 ;
        RECT  0 10.08 0.192 10.104 ;
    END
  END i[77]
  PIN i[78]
    DIRECTION INPUT ;
    USE SIGNAL ;
    PORT
      LAYER M4 ;
        RECT  0 10.176 0.192 10.2 ;
    END
  END i[78]
  PIN i[79]
    DIRECTION INPUT ;
    USE SIGNAL ;
    PORT
      LAYER M4 ;
        RECT  0 10.272 0.192 10.296 ;
    END
  END i[79]
  PIN i[7]
    DIRECTION INPUT ;
    USE SIGNAL ;
    PORT
      LAYER M4 ;
        RECT  0 2.928 0.192 2.952 ;
    END
  END i[7]
  PIN i[80]
    DIRECTION INPUT ;
    USE SIGNAL ;
    PORT
      LAYER M4 ;
        RECT  0 10.368 0.192 10.392 ;
    END
  END i[80]
  PIN i[81]
    DIRECTION INPUT ;
    USE SIGNAL ;
    PORT
      LAYER M4 ;
        RECT  0 10.464 0.192 10.488 ;
    END
  END i[81]
  PIN i[82]
    DIRECTION INPUT ;
    USE SIGNAL ;
    PORT
      LAYER M4 ;
        RECT  0 10.56 0.192 10.584 ;
    END
  END i[82]
  PIN i[83]
    DIRECTION INPUT ;
    USE SIGNAL ;
    PORT
      LAYER M4 ;
        RECT  0 10.656 0.192 10.68 ;
    END
  END i[83]
  PIN i[84]
    DIRECTION INPUT ;
    USE SIGNAL ;
    PORT
      LAYER M4 ;
        RECT  0 10.752 0.192 10.776 ;
    END
  END i[84]
  PIN i[85]
    DIRECTION INPUT ;
    USE SIGNAL ;
    PORT
      LAYER M4 ;
        RECT  0 10.848 0.192 10.872 ;
    END
  END i[85]
  PIN i[86]
    DIRECTION INPUT ;
    USE SIGNAL ;
    PORT
      LAYER M4 ;
        RECT  0 10.992 0.192 11.016 ;
    END
  END i[86]
  PIN i[87]
    DIRECTION INPUT ;
    USE SIGNAL ;
    PORT
      LAYER M4 ;
        RECT  0 11.088 0.192 11.112 ;
    END
  END i[87]
  PIN i[88]
    DIRECTION INPUT ;
    USE SIGNAL ;
    PORT
      LAYER M4 ;
        RECT  0 11.184 0.192 11.208 ;
    END
  END i[88]
  PIN i[89]
    DIRECTION INPUT ;
    USE SIGNAL ;
    PORT
      LAYER M4 ;
        RECT  0 11.28 0.192 11.304 ;
    END
  END i[89]
  PIN i[8]
    DIRECTION INPUT ;
    USE SIGNAL ;
    PORT
      LAYER M4 ;
        RECT  0 3.024 0.192 3.048 ;
    END
  END i[8]
  PIN i[90]
    DIRECTION INPUT ;
    USE SIGNAL ;
    PORT
      LAYER M4 ;
        RECT  0 11.376 0.192 11.4 ;
    END
  END i[90]
  PIN i[91]
    DIRECTION INPUT ;
    USE SIGNAL ;
    PORT
      LAYER M4 ;
        RECT  0 11.472 0.192 11.496 ;
    END
  END i[91]
  PIN i[92]
    DIRECTION INPUT ;
    USE SIGNAL ;
    PORT
      LAYER M4 ;
        RECT  0 11.568 0.192 11.592 ;
    END
  END i[92]
  PIN i[93]
    DIRECTION INPUT ;
    USE SIGNAL ;
    PORT
      LAYER M4 ;
        RECT  0 11.664 0.192 11.688 ;
    END
  END i[93]
  PIN i[94]
    DIRECTION INPUT ;
    USE SIGNAL ;
    PORT
      LAYER M4 ;
        RECT  0 11.808 0.192 11.832 ;
    END
  END i[94]
  PIN i[95]
    DIRECTION INPUT ;
    USE SIGNAL ;
    PORT
      LAYER M4 ;
        RECT  0 11.904 0.192 11.928 ;
    END
  END i[95]
  PIN i[96]
    DIRECTION INPUT ;
    USE SIGNAL ;
    PORT
      LAYER M4 ;
        RECT  0 12 0.192 12.024 ;
    END
  END i[96]
  PIN i[97]
    DIRECTION INPUT ;
    USE SIGNAL ;
    PORT
      LAYER M4 ;
        RECT  0 12.096 0.192 12.12 ;
    END
  END i[97]
  PIN i[98]
    DIRECTION INPUT ;
    USE SIGNAL ;
    PORT
      LAYER M4 ;
        RECT  0 12.192 0.192 12.216 ;
    END
  END i[98]
  PIN i[99]
    DIRECTION INPUT ;
    USE SIGNAL ;
    PORT
      LAYER M4 ;
        RECT  0 12.288 0.192 12.312 ;
    END
  END i[99]
  PIN i[9]
    DIRECTION INPUT ;
    USE SIGNAL ;
    PORT
      LAYER M4 ;
        RECT  0 3.12 0.192 3.144 ;
    END
  END i[9]
  PIN o[0]
    DIRECTION OUTPUT ;
    USE SIGNAL ;
    PORT
      LAYER M4 ;
        RECT  17.088 2.208 17.28 2.232 ;
    END
  END o[0]
  PIN o[100]
    DIRECTION OUTPUT ;
    USE SIGNAL ;
    PORT
      LAYER M4 ;
        RECT  17.088 12.384 17.28 12.408 ;
    END
  END o[100]
  PIN o[101]
    DIRECTION OUTPUT ;
    USE SIGNAL ;
    PORT
      LAYER M4 ;
        RECT  17.088 12.48 17.28 12.504 ;
    END
  END o[101]
  PIN o[102]
    DIRECTION OUTPUT ;
    USE SIGNAL ;
    PORT
      LAYER M4 ;
        RECT  17.088 12.624 17.28 12.648 ;
    END
  END o[102]
  PIN o[103]
    DIRECTION OUTPUT ;
    USE SIGNAL ;
    PORT
      LAYER M4 ;
        RECT  17.088 12.72 17.28 12.744 ;
    END
  END o[103]
  PIN o[104]
    DIRECTION OUTPUT ;
    USE SIGNAL ;
    PORT
      LAYER M4 ;
        RECT  17.088 12.816 17.28 12.84 ;
    END
  END o[104]
  PIN o[105]
    DIRECTION OUTPUT ;
    USE SIGNAL ;
    PORT
      LAYER M4 ;
        RECT  17.088 12.912 17.28 12.936 ;
    END
  END o[105]
  PIN o[106]
    DIRECTION OUTPUT ;
    USE SIGNAL ;
    PORT
      LAYER M4 ;
        RECT  17.088 13.008 17.28 13.032 ;
    END
  END o[106]
  PIN o[107]
    DIRECTION OUTPUT ;
    USE SIGNAL ;
    PORT
      LAYER M4 ;
        RECT  17.088 13.104 17.28 13.128 ;
    END
  END o[107]
  PIN o[108]
    DIRECTION OUTPUT ;
    USE SIGNAL ;
    PORT
      LAYER M4 ;
        RECT  17.088 13.2 17.28 13.224 ;
    END
  END o[108]
  PIN o[109]
    DIRECTION OUTPUT ;
    USE SIGNAL ;
    PORT
      LAYER M4 ;
        RECT  17.088 13.296 17.28 13.32 ;
    END
  END o[109]
  PIN o[10]
    DIRECTION OUTPUT ;
    USE SIGNAL ;
    PORT
      LAYER M4 ;
        RECT  17.088 3.264 17.28 3.288 ;
    END
  END o[10]
  PIN o[110]
    DIRECTION OUTPUT ;
    USE SIGNAL ;
    PORT
      LAYER M4 ;
        RECT  17.088 13.392 17.28 13.416 ;
    END
  END o[110]
  PIN o[111]
    DIRECTION OUTPUT ;
    USE SIGNAL ;
    PORT
      LAYER M4 ;
        RECT  17.088 13.536 17.28 13.56 ;
    END
  END o[111]
  PIN o[112]
    DIRECTION OUTPUT ;
    USE SIGNAL ;
    PORT
      LAYER M4 ;
        RECT  17.088 13.632 17.28 13.656 ;
    END
  END o[112]
  PIN o[113]
    DIRECTION OUTPUT ;
    USE SIGNAL ;
    PORT
      LAYER M4 ;
        RECT  17.088 13.728 17.28 13.752 ;
    END
  END o[113]
  PIN o[114]
    DIRECTION OUTPUT ;
    USE SIGNAL ;
    PORT
      LAYER M4 ;
        RECT  17.088 13.824 17.28 13.848 ;
    END
  END o[114]
  PIN o[115]
    DIRECTION OUTPUT ;
    USE SIGNAL ;
    PORT
      LAYER M4 ;
        RECT  17.088 13.92 17.28 13.944 ;
    END
  END o[115]
  PIN o[116]
    DIRECTION OUTPUT ;
    USE SIGNAL ;
    PORT
      LAYER M4 ;
        RECT  17.088 14.016 17.28 14.04 ;
    END
  END o[116]
  PIN o[117]
    DIRECTION OUTPUT ;
    USE SIGNAL ;
    PORT
      LAYER M4 ;
        RECT  17.088 14.112 17.28 14.136 ;
    END
  END o[117]
  PIN o[118]
    DIRECTION OUTPUT ;
    USE SIGNAL ;
    PORT
      LAYER M4 ;
        RECT  17.088 14.208 17.28 14.232 ;
    END
  END o[118]
  PIN o[119]
    DIRECTION OUTPUT ;
    USE SIGNAL ;
    PORT
      LAYER M4 ;
        RECT  17.088 14.352 17.28 14.376 ;
    END
  END o[119]
  PIN o[11]
    DIRECTION OUTPUT ;
    USE SIGNAL ;
    PORT
      LAYER M4 ;
        RECT  17.088 3.36 17.28 3.384 ;
    END
  END o[11]
  PIN o[120]
    DIRECTION OUTPUT ;
    USE SIGNAL ;
    PORT
      LAYER M4 ;
        RECT  17.088 14.448 17.28 14.472 ;
    END
  END o[120]
  PIN o[121]
    DIRECTION OUTPUT ;
    USE SIGNAL ;
    PORT
      LAYER M4 ;
        RECT  17.088 14.544 17.28 14.568 ;
    END
  END o[121]
  PIN o[122]
    DIRECTION OUTPUT ;
    USE SIGNAL ;
    PORT
      LAYER M4 ;
        RECT  17.088 14.64 17.28 14.664 ;
    END
  END o[122]
  PIN o[123]
    DIRECTION OUTPUT ;
    USE SIGNAL ;
    PORT
      LAYER M4 ;
        RECT  17.088 14.736 17.28 14.76 ;
    END
  END o[123]
  PIN o[124]
    DIRECTION OUTPUT ;
    USE SIGNAL ;
    PORT
      LAYER M4 ;
        RECT  17.088 14.832 17.28 14.856 ;
    END
  END o[124]
  PIN o[125]
    DIRECTION OUTPUT ;
    USE SIGNAL ;
    PORT
      LAYER M4 ;
        RECT  17.088 14.928 17.28 14.952 ;
    END
  END o[125]
  PIN o[126]
    DIRECTION OUTPUT ;
    USE SIGNAL ;
    PORT
      LAYER M4 ;
        RECT  17.088 15.024 17.28 15.048 ;
    END
  END o[126]
  PIN o[127]
    DIRECTION OUTPUT ;
    USE SIGNAL ;
    PORT
      LAYER M4 ;
        RECT  17.088 15.12 17.28 15.144 ;
    END
  END o[127]
  PIN o[128]
    DIRECTION OUTPUT ;
    USE SIGNAL ;
    PORT
      LAYER M4 ;
        RECT  17.088 15.264 17.28 15.288 ;
    END
  END o[128]
  PIN o[129]
    DIRECTION OUTPUT ;
    USE SIGNAL ;
    PORT
      LAYER M4 ;
        RECT  17.088 15.36 17.28 15.384 ;
    END
  END o[129]
  PIN o[12]
    DIRECTION OUTPUT ;
    USE SIGNAL ;
    PORT
      LAYER M4 ;
        RECT  17.088 3.456 17.28 3.48 ;
    END
  END o[12]
  PIN o[130]
    DIRECTION OUTPUT ;
    USE SIGNAL ;
    PORT
      LAYER M4 ;
        RECT  17.088 15.456 17.28 15.48 ;
    END
  END o[130]
  PIN o[131]
    DIRECTION OUTPUT ;
    USE SIGNAL ;
    PORT
      LAYER M4 ;
        RECT  17.088 15.552 17.28 15.576 ;
    END
  END o[131]
  PIN o[132]
    DIRECTION OUTPUT ;
    USE SIGNAL ;
    PORT
      LAYER M4 ;
        RECT  17.088 15.648 17.28 15.672 ;
    END
  END o[132]
  PIN o[133]
    DIRECTION OUTPUT ;
    USE SIGNAL ;
    PORT
      LAYER M4 ;
        RECT  17.088 15.744 17.28 15.768 ;
    END
  END o[133]
  PIN o[134]
    DIRECTION OUTPUT ;
    USE SIGNAL ;
    PORT
      LAYER M4 ;
        RECT  17.088 15.84 17.28 15.864 ;
    END
  END o[134]
  PIN o[135]
    DIRECTION OUTPUT ;
    USE SIGNAL ;
    PORT
      LAYER M4 ;
        RECT  17.088 15.936 17.28 15.96 ;
    END
  END o[135]
  PIN o[136]
    DIRECTION OUTPUT ;
    USE SIGNAL ;
    PORT
      LAYER M4 ;
        RECT  17.088 16.08 17.28 16.104 ;
    END
  END o[136]
  PIN o[137]
    DIRECTION OUTPUT ;
    USE SIGNAL ;
    PORT
      LAYER M4 ;
        RECT  17.088 16.176 17.28 16.2 ;
    END
  END o[137]
  PIN o[138]
    DIRECTION OUTPUT ;
    USE SIGNAL ;
    PORT
      LAYER M4 ;
        RECT  17.088 16.272 17.28 16.296 ;
    END
  END o[138]
  PIN o[139]
    DIRECTION OUTPUT ;
    USE SIGNAL ;
    PORT
      LAYER M4 ;
        RECT  17.088 16.368 17.28 16.392 ;
    END
  END o[139]
  PIN o[13]
    DIRECTION OUTPUT ;
    USE SIGNAL ;
    PORT
      LAYER M4 ;
        RECT  17.088 3.552 17.28 3.576 ;
    END
  END o[13]
  PIN o[140]
    DIRECTION OUTPUT ;
    USE SIGNAL ;
    PORT
      LAYER M4 ;
        RECT  17.088 16.464 17.28 16.488 ;
    END
  END o[140]
  PIN o[141]
    DIRECTION OUTPUT ;
    USE SIGNAL ;
    PORT
      LAYER M4 ;
        RECT  17.088 16.56 17.28 16.584 ;
    END
  END o[141]
  PIN o[142]
    DIRECTION OUTPUT ;
    USE SIGNAL ;
    PORT
      LAYER M4 ;
        RECT  17.088 16.656 17.28 16.68 ;
    END
  END o[142]
  PIN o[143]
    DIRECTION OUTPUT ;
    USE SIGNAL ;
    PORT
      LAYER M4 ;
        RECT  17.088 16.752 17.28 16.776 ;
    END
  END o[143]
  PIN o[144]
    DIRECTION OUTPUT ;
    USE SIGNAL ;
    PORT
      LAYER M4 ;
        RECT  17.088 16.896 17.28 16.92 ;
    END
  END o[144]
  PIN o[145]
    DIRECTION OUTPUT ;
    USE SIGNAL ;
    PORT
      LAYER M4 ;
        RECT  17.088 16.992 17.28 17.016 ;
    END
  END o[145]
  PIN o[146]
    DIRECTION OUTPUT ;
    USE SIGNAL ;
    PORT
      LAYER M4 ;
        RECT  17.088 17.088 17.28 17.112 ;
    END
  END o[146]
  PIN o[147]
    DIRECTION OUTPUT ;
    USE SIGNAL ;
    PORT
      LAYER M4 ;
        RECT  17.088 17.184 17.28 17.208 ;
    END
  END o[147]
  PIN o[148]
    DIRECTION OUTPUT ;
    USE SIGNAL ;
    PORT
      LAYER M4 ;
        RECT  17.088 17.28 17.28 17.304 ;
    END
  END o[148]
  PIN o[149]
    DIRECTION OUTPUT ;
    USE SIGNAL ;
    PORT
      LAYER M4 ;
        RECT  17.088 17.376 17.28 17.4 ;
    END
  END o[149]
  PIN o[14]
    DIRECTION OUTPUT ;
    USE SIGNAL ;
    PORT
      LAYER M4 ;
        RECT  17.088 3.648 17.28 3.672 ;
    END
  END o[14]
  PIN o[150]
    DIRECTION OUTPUT ;
    USE SIGNAL ;
    PORT
      LAYER M4 ;
        RECT  17.088 17.472 17.28 17.496 ;
    END
  END o[150]
  PIN o[151]
    DIRECTION OUTPUT ;
    USE SIGNAL ;
    PORT
      LAYER M4 ;
        RECT  17.088 17.568 17.28 17.592 ;
    END
  END o[151]
  PIN o[152]
    DIRECTION OUTPUT ;
    USE SIGNAL ;
    PORT
      LAYER M4 ;
        RECT  17.088 17.664 17.28 17.688 ;
    END
  END o[152]
  PIN o[153]
    DIRECTION OUTPUT ;
    USE SIGNAL ;
    PORT
      LAYER M4 ;
        RECT  17.088 17.808 17.28 17.832 ;
    END
  END o[153]
  PIN o[154]
    DIRECTION OUTPUT ;
    USE SIGNAL ;
    PORT
      LAYER M4 ;
        RECT  17.088 17.904 17.28 17.928 ;
    END
  END o[154]
  PIN o[155]
    DIRECTION OUTPUT ;
    USE SIGNAL ;
    PORT
      LAYER M4 ;
        RECT  17.088 18 17.28 18.024 ;
    END
  END o[155]
  PIN o[156]
    DIRECTION OUTPUT ;
    USE SIGNAL ;
    PORT
      LAYER M4 ;
        RECT  17.088 18.096 17.28 18.12 ;
    END
  END o[156]
  PIN o[157]
    DIRECTION OUTPUT ;
    USE SIGNAL ;
    PORT
      LAYER M4 ;
        RECT  17.088 18.192 17.28 18.216 ;
    END
  END o[157]
  PIN o[158]
    DIRECTION OUTPUT ;
    USE SIGNAL ;
    PORT
      LAYER M4 ;
        RECT  17.088 18.288 17.28 18.312 ;
    END
  END o[158]
  PIN o[159]
    DIRECTION OUTPUT ;
    USE SIGNAL ;
    PORT
      LAYER M4 ;
        RECT  17.088 18.384 17.28 18.408 ;
    END
  END o[159]
  PIN o[15]
    DIRECTION OUTPUT ;
    USE SIGNAL ;
    PORT
      LAYER M4 ;
        RECT  17.088 3.744 17.28 3.768 ;
    END
  END o[15]
  PIN o[160]
    DIRECTION OUTPUT ;
    USE SIGNAL ;
    PORT
      LAYER M4 ;
        RECT  17.088 18.48 17.28 18.504 ;
    END
  END o[160]
  PIN o[161]
    DIRECTION OUTPUT ;
    USE SIGNAL ;
    PORT
      LAYER M4 ;
        RECT  17.088 18.624 17.28 18.648 ;
    END
  END o[161]
  PIN o[162]
    DIRECTION OUTPUT ;
    USE SIGNAL ;
    PORT
      LAYER M4 ;
        RECT  17.088 18.72 17.28 18.744 ;
    END
  END o[162]
  PIN o[163]
    DIRECTION OUTPUT ;
    USE SIGNAL ;
    PORT
      LAYER M4 ;
        RECT  17.088 18.816 17.28 18.84 ;
    END
  END o[163]
  PIN o[164]
    DIRECTION OUTPUT ;
    USE SIGNAL ;
    PORT
      LAYER M4 ;
        RECT  17.088 18.912 17.28 18.936 ;
    END
  END o[164]
  PIN o[165]
    DIRECTION OUTPUT ;
    USE SIGNAL ;
    PORT
      LAYER M4 ;
        RECT  17.088 19.008 17.28 19.032 ;
    END
  END o[165]
  PIN o[166]
    DIRECTION OUTPUT ;
    USE SIGNAL ;
    PORT
      LAYER M4 ;
        RECT  17.088 19.104 17.28 19.128 ;
    END
  END o[166]
  PIN o[167]
    DIRECTION OUTPUT ;
    USE SIGNAL ;
    PORT
      LAYER M4 ;
        RECT  17.088 19.2 17.28 19.224 ;
    END
  END o[167]
  PIN o[168]
    DIRECTION OUTPUT ;
    USE SIGNAL ;
    PORT
      LAYER M4 ;
        RECT  17.088 19.296 17.28 19.32 ;
    END
  END o[168]
  PIN o[169]
    DIRECTION OUTPUT ;
    USE SIGNAL ;
    PORT
      LAYER M4 ;
        RECT  17.088 19.44 17.28 19.464 ;
    END
  END o[169]
  PIN o[16]
    DIRECTION OUTPUT ;
    USE SIGNAL ;
    PORT
      LAYER M4 ;
        RECT  17.088 3.84 17.28 3.864 ;
    END
  END o[16]
  PIN o[170]
    DIRECTION OUTPUT ;
    USE SIGNAL ;
    PORT
      LAYER M4 ;
        RECT  17.088 19.536 17.28 19.56 ;
    END
  END o[170]
  PIN o[171]
    DIRECTION OUTPUT ;
    USE SIGNAL ;
    PORT
      LAYER M4 ;
        RECT  17.088 19.632 17.28 19.656 ;
    END
  END o[171]
  PIN o[172]
    DIRECTION OUTPUT ;
    USE SIGNAL ;
    PORT
      LAYER M4 ;
        RECT  17.088 19.728 17.28 19.752 ;
    END
  END o[172]
  PIN o[173]
    DIRECTION OUTPUT ;
    USE SIGNAL ;
    PORT
      LAYER M4 ;
        RECT  17.088 19.824 17.28 19.848 ;
    END
  END o[173]
  PIN o[174]
    DIRECTION OUTPUT ;
    USE SIGNAL ;
    PORT
      LAYER M4 ;
        RECT  17.088 19.92 17.28 19.944 ;
    END
  END o[174]
  PIN o[175]
    DIRECTION OUTPUT ;
    USE SIGNAL ;
    PORT
      LAYER M4 ;
        RECT  17.088 20.016 17.28 20.04 ;
    END
  END o[175]
  PIN o[176]
    DIRECTION OUTPUT ;
    USE SIGNAL ;
    PORT
      LAYER M4 ;
        RECT  17.088 20.112 17.28 20.136 ;
    END
  END o[176]
  PIN o[177]
    DIRECTION OUTPUT ;
    USE SIGNAL ;
    PORT
      LAYER M4 ;
        RECT  17.088 20.208 17.28 20.232 ;
    END
  END o[177]
  PIN o[178]
    DIRECTION OUTPUT ;
    USE SIGNAL ;
    PORT
      LAYER M4 ;
        RECT  17.088 20.352 17.28 20.376 ;
    END
  END o[178]
  PIN o[179]
    DIRECTION OUTPUT ;
    USE SIGNAL ;
    PORT
      LAYER M4 ;
        RECT  17.088 20.448 17.28 20.472 ;
    END
  END o[179]
  PIN o[17]
    DIRECTION OUTPUT ;
    USE SIGNAL ;
    PORT
      LAYER M4 ;
        RECT  17.088 3.936 17.28 3.96 ;
    END
  END o[17]
  PIN o[180]
    DIRECTION OUTPUT ;
    USE SIGNAL ;
    PORT
      LAYER M4 ;
        RECT  17.088 20.544 17.28 20.568 ;
    END
  END o[180]
  PIN o[181]
    DIRECTION OUTPUT ;
    USE SIGNAL ;
    PORT
      LAYER M4 ;
        RECT  17.088 20.64 17.28 20.664 ;
    END
  END o[181]
  PIN o[182]
    DIRECTION OUTPUT ;
    USE SIGNAL ;
    PORT
      LAYER M4 ;
        RECT  17.088 20.736 17.28 20.76 ;
    END
  END o[182]
  PIN o[183]
    DIRECTION OUTPUT ;
    USE SIGNAL ;
    PORT
      LAYER M4 ;
        RECT  17.088 20.832 17.28 20.856 ;
    END
  END o[183]
  PIN o[184]
    DIRECTION OUTPUT ;
    USE SIGNAL ;
    PORT
      LAYER M4 ;
        RECT  17.088 20.928 17.28 20.952 ;
    END
  END o[184]
  PIN o[185]
    DIRECTION OUTPUT ;
    USE SIGNAL ;
    PORT
      LAYER M4 ;
        RECT  17.088 21.024 17.28 21.048 ;
    END
  END o[185]
  PIN o[186]
    DIRECTION OUTPUT ;
    USE SIGNAL ;
    PORT
      LAYER M4 ;
        RECT  17.088 21.168 17.28 21.192 ;
    END
  END o[186]
  PIN o[187]
    DIRECTION OUTPUT ;
    USE SIGNAL ;
    PORT
      LAYER M4 ;
        RECT  17.088 21.264 17.28 21.288 ;
    END
  END o[187]
  PIN o[188]
    DIRECTION OUTPUT ;
    USE SIGNAL ;
    PORT
      LAYER M4 ;
        RECT  17.088 21.36 17.28 21.384 ;
    END
  END o[188]
  PIN o[189]
    DIRECTION OUTPUT ;
    USE SIGNAL ;
    PORT
      LAYER M4 ;
        RECT  17.088 21.456 17.28 21.48 ;
    END
  END o[189]
  PIN o[18]
    DIRECTION OUTPUT ;
    USE SIGNAL ;
    PORT
      LAYER M4 ;
        RECT  17.088 4.032 17.28 4.056 ;
    END
  END o[18]
  PIN o[190]
    DIRECTION OUTPUT ;
    USE SIGNAL ;
    PORT
      LAYER M4 ;
        RECT  17.088 21.552 17.28 21.576 ;
    END
  END o[190]
  PIN o[191]
    DIRECTION OUTPUT ;
    USE SIGNAL ;
    PORT
      LAYER M4 ;
        RECT  17.088 21.648 17.28 21.672 ;
    END
  END o[191]
  PIN o[192]
    DIRECTION OUTPUT ;
    USE SIGNAL ;
    PORT
      LAYER M4 ;
        RECT  17.088 21.744 17.28 21.768 ;
    END
  END o[192]
  PIN o[193]
    DIRECTION OUTPUT ;
    USE SIGNAL ;
    PORT
      LAYER M4 ;
        RECT  17.088 21.84 17.28 21.864 ;
    END
  END o[193]
  PIN o[194]
    DIRECTION OUTPUT ;
    USE SIGNAL ;
    PORT
      LAYER M4 ;
        RECT  17.088 21.984 17.28 22.008 ;
    END
  END o[194]
  PIN o[195]
    DIRECTION OUTPUT ;
    USE SIGNAL ;
    PORT
      LAYER M4 ;
        RECT  17.088 22.08 17.28 22.104 ;
    END
  END o[195]
  PIN o[196]
    DIRECTION OUTPUT ;
    USE SIGNAL ;
    PORT
      LAYER M4 ;
        RECT  17.088 22.176 17.28 22.2 ;
    END
  END o[196]
  PIN o[197]
    DIRECTION OUTPUT ;
    USE SIGNAL ;
    PORT
      LAYER M4 ;
        RECT  17.088 22.272 17.28 22.296 ;
    END
  END o[197]
  PIN o[198]
    DIRECTION OUTPUT ;
    USE SIGNAL ;
    PORT
      LAYER M4 ;
        RECT  17.088 22.368 17.28 22.392 ;
    END
  END o[198]
  PIN o[199]
    DIRECTION OUTPUT ;
    USE SIGNAL ;
    PORT
      LAYER M4 ;
        RECT  17.088 22.464 17.28 22.488 ;
    END
  END o[199]
  PIN o[19]
    DIRECTION OUTPUT ;
    USE SIGNAL ;
    PORT
      LAYER M4 ;
        RECT  17.088 4.176 17.28 4.2 ;
    END
  END o[19]
  PIN o[1]
    DIRECTION OUTPUT ;
    USE SIGNAL ;
    PORT
      LAYER M4 ;
        RECT  17.088 2.304 17.28 2.328 ;
    END
  END o[1]
  PIN o[200]
    DIRECTION OUTPUT ;
    USE SIGNAL ;
    PORT
      LAYER M4 ;
        RECT  17.088 22.56 17.28 22.584 ;
    END
  END o[200]
  PIN o[201]
    DIRECTION OUTPUT ;
    USE SIGNAL ;
    PORT
      LAYER M4 ;
        RECT  17.088 22.656 17.28 22.68 ;
    END
  END o[201]
  PIN o[202]
    DIRECTION OUTPUT ;
    USE SIGNAL ;
    PORT
      LAYER M4 ;
        RECT  17.088 22.752 17.28 22.776 ;
    END
  END o[202]
  PIN o[203]
    DIRECTION OUTPUT ;
    USE SIGNAL ;
    PORT
      LAYER M4 ;
        RECT  17.088 22.896 17.28 22.92 ;
    END
  END o[203]
  PIN o[204]
    DIRECTION OUTPUT ;
    USE SIGNAL ;
    PORT
      LAYER M4 ;
        RECT  17.088 22.992 17.28 23.016 ;
    END
  END o[204]
  PIN o[205]
    DIRECTION OUTPUT ;
    USE SIGNAL ;
    PORT
      LAYER M4 ;
        RECT  17.088 23.088 17.28 23.112 ;
    END
  END o[205]
  PIN o[206]
    DIRECTION OUTPUT ;
    USE SIGNAL ;
    PORT
      LAYER M4 ;
        RECT  17.088 23.184 17.28 23.208 ;
    END
  END o[206]
  PIN o[207]
    DIRECTION OUTPUT ;
    USE SIGNAL ;
    PORT
      LAYER M4 ;
        RECT  17.088 23.28 17.28 23.304 ;
    END
  END o[207]
  PIN o[208]
    DIRECTION OUTPUT ;
    USE SIGNAL ;
    PORT
      LAYER M4 ;
        RECT  17.088 23.376 17.28 23.4 ;
    END
  END o[208]
  PIN o[209]
    DIRECTION OUTPUT ;
    USE SIGNAL ;
    PORT
      LAYER M4 ;
        RECT  17.088 23.472 17.28 23.496 ;
    END
  END o[209]
  PIN o[20]
    DIRECTION OUTPUT ;
    USE SIGNAL ;
    PORT
      LAYER M4 ;
        RECT  17.088 4.272 17.28 4.296 ;
    END
  END o[20]
  PIN o[210]
    DIRECTION OUTPUT ;
    USE SIGNAL ;
    PORT
      LAYER M4 ;
        RECT  17.088 23.568 17.28 23.592 ;
    END
  END o[210]
  PIN o[211]
    DIRECTION OUTPUT ;
    USE SIGNAL ;
    PORT
      LAYER M4 ;
        RECT  17.088 23.712 17.28 23.736 ;
    END
  END o[211]
  PIN o[212]
    DIRECTION OUTPUT ;
    USE SIGNAL ;
    PORT
      LAYER M4 ;
        RECT  17.088 23.808 17.28 23.832 ;
    END
  END o[212]
  PIN o[213]
    DIRECTION OUTPUT ;
    USE SIGNAL ;
    PORT
      LAYER M4 ;
        RECT  17.088 23.904 17.28 23.928 ;
    END
  END o[213]
  PIN o[214]
    DIRECTION OUTPUT ;
    USE SIGNAL ;
    PORT
      LAYER M4 ;
        RECT  17.088 24 17.28 24.024 ;
    END
  END o[214]
  PIN o[215]
    DIRECTION OUTPUT ;
    USE SIGNAL ;
    PORT
      LAYER M4 ;
        RECT  17.088 24.096 17.28 24.12 ;
    END
  END o[215]
  PIN o[216]
    DIRECTION OUTPUT ;
    USE SIGNAL ;
    PORT
      LAYER M4 ;
        RECT  17.088 24.192 17.28 24.216 ;
    END
  END o[216]
  PIN o[217]
    DIRECTION OUTPUT ;
    USE SIGNAL ;
    PORT
      LAYER M4 ;
        RECT  17.088 24.288 17.28 24.312 ;
    END
  END o[217]
  PIN o[218]
    DIRECTION OUTPUT ;
    USE SIGNAL ;
    PORT
      LAYER M4 ;
        RECT  17.088 24.384 17.28 24.408 ;
    END
  END o[218]
  PIN o[219]
    DIRECTION OUTPUT ;
    USE SIGNAL ;
    PORT
      LAYER M4 ;
        RECT  17.088 24.48 17.28 24.504 ;
    END
  END o[219]
  PIN o[21]
    DIRECTION OUTPUT ;
    USE SIGNAL ;
    PORT
      LAYER M4 ;
        RECT  17.088 4.368 17.28 4.392 ;
    END
  END o[21]
  PIN o[220]
    DIRECTION OUTPUT ;
    USE SIGNAL ;
    PORT
      LAYER M4 ;
        RECT  17.088 24.624 17.28 24.648 ;
    END
  END o[220]
  PIN o[221]
    DIRECTION OUTPUT ;
    USE SIGNAL ;
    PORT
      LAYER M4 ;
        RECT  17.088 24.72 17.28 24.744 ;
    END
  END o[221]
  PIN o[222]
    DIRECTION OUTPUT ;
    USE SIGNAL ;
    PORT
      LAYER M4 ;
        RECT  17.088 24.816 17.28 24.84 ;
    END
  END o[222]
  PIN o[223]
    DIRECTION OUTPUT ;
    USE SIGNAL ;
    PORT
      LAYER M4 ;
        RECT  17.088 24.912 17.28 24.936 ;
    END
  END o[223]
  PIN o[224]
    DIRECTION OUTPUT ;
    USE SIGNAL ;
    PORT
      LAYER M4 ;
        RECT  17.088 25.008 17.28 25.032 ;
    END
  END o[224]
  PIN o[225]
    DIRECTION OUTPUT ;
    USE SIGNAL ;
    PORT
      LAYER M4 ;
        RECT  17.088 25.104 17.28 25.128 ;
    END
  END o[225]
  PIN o[226]
    DIRECTION OUTPUT ;
    USE SIGNAL ;
    PORT
      LAYER M4 ;
        RECT  17.088 25.2 17.28 25.224 ;
    END
  END o[226]
  PIN o[227]
    DIRECTION OUTPUT ;
    USE SIGNAL ;
    PORT
      LAYER M4 ;
        RECT  17.088 25.296 17.28 25.32 ;
    END
  END o[227]
  PIN o[228]
    DIRECTION OUTPUT ;
    USE SIGNAL ;
    PORT
      LAYER M4 ;
        RECT  17.088 25.44 17.28 25.464 ;
    END
  END o[228]
  PIN o[229]
    DIRECTION OUTPUT ;
    USE SIGNAL ;
    PORT
      LAYER M4 ;
        RECT  17.088 25.536 17.28 25.56 ;
    END
  END o[229]
  PIN o[22]
    DIRECTION OUTPUT ;
    USE SIGNAL ;
    PORT
      LAYER M4 ;
        RECT  17.088 4.464 17.28 4.488 ;
    END
  END o[22]
  PIN o[230]
    DIRECTION OUTPUT ;
    USE SIGNAL ;
    PORT
      LAYER M4 ;
        RECT  17.088 25.632 17.28 25.656 ;
    END
  END o[230]
  PIN o[231]
    DIRECTION OUTPUT ;
    USE SIGNAL ;
    PORT
      LAYER M4 ;
        RECT  17.088 25.728 17.28 25.752 ;
    END
  END o[231]
  PIN o[232]
    DIRECTION OUTPUT ;
    USE SIGNAL ;
    PORT
      LAYER M4 ;
        RECT  17.088 25.824 17.28 25.848 ;
    END
  END o[232]
  PIN o[233]
    DIRECTION OUTPUT ;
    USE SIGNAL ;
    PORT
      LAYER M4 ;
        RECT  17.088 25.92 17.28 25.944 ;
    END
  END o[233]
  PIN o[234]
    DIRECTION OUTPUT ;
    USE SIGNAL ;
    PORT
      LAYER M4 ;
        RECT  17.088 26.016 17.28 26.04 ;
    END
  END o[234]
  PIN o[235]
    DIRECTION OUTPUT ;
    USE SIGNAL ;
    PORT
      LAYER M4 ;
        RECT  17.088 26.112 17.28 26.136 ;
    END
  END o[235]
  PIN o[236]
    DIRECTION OUTPUT ;
    USE SIGNAL ;
    PORT
      LAYER M4 ;
        RECT  17.088 26.256 17.28 26.28 ;
    END
  END o[236]
  PIN o[237]
    DIRECTION OUTPUT ;
    USE SIGNAL ;
    PORT
      LAYER M4 ;
        RECT  17.088 26.352 17.28 26.376 ;
    END
  END o[237]
  PIN o[238]
    DIRECTION OUTPUT ;
    USE SIGNAL ;
    PORT
      LAYER M4 ;
        RECT  17.088 26.448 17.28 26.472 ;
    END
  END o[238]
  PIN o[239]
    DIRECTION OUTPUT ;
    USE SIGNAL ;
    PORT
      LAYER M4 ;
        RECT  17.088 26.544 17.28 26.568 ;
    END
  END o[239]
  PIN o[23]
    DIRECTION OUTPUT ;
    USE SIGNAL ;
    PORT
      LAYER M4 ;
        RECT  17.088 4.56 17.28 4.584 ;
    END
  END o[23]
  PIN o[240]
    DIRECTION OUTPUT ;
    USE SIGNAL ;
    PORT
      LAYER M4 ;
        RECT  17.088 26.64 17.28 26.664 ;
    END
  END o[240]
  PIN o[241]
    DIRECTION OUTPUT ;
    USE SIGNAL ;
    PORT
      LAYER M4 ;
        RECT  17.088 26.736 17.28 26.76 ;
    END
  END o[241]
  PIN o[242]
    DIRECTION OUTPUT ;
    USE SIGNAL ;
    PORT
      LAYER M4 ;
        RECT  17.088 26.832 17.28 26.856 ;
    END
  END o[242]
  PIN o[243]
    DIRECTION OUTPUT ;
    USE SIGNAL ;
    PORT
      LAYER M4 ;
        RECT  17.088 26.928 17.28 26.952 ;
    END
  END o[243]
  PIN o[244]
    DIRECTION OUTPUT ;
    USE SIGNAL ;
    PORT
      LAYER M4 ;
        RECT  17.088 27.024 17.28 27.048 ;
    END
  END o[244]
  PIN o[245]
    DIRECTION OUTPUT ;
    USE SIGNAL ;
    PORT
      LAYER M4 ;
        RECT  17.088 27.168 17.28 27.192 ;
    END
  END o[245]
  PIN o[246]
    DIRECTION OUTPUT ;
    USE SIGNAL ;
    PORT
      LAYER M4 ;
        RECT  17.088 27.264 17.28 27.288 ;
    END
  END o[246]
  PIN o[247]
    DIRECTION OUTPUT ;
    USE SIGNAL ;
    PORT
      LAYER M4 ;
        RECT  17.088 27.36 17.28 27.384 ;
    END
  END o[247]
  PIN o[248]
    DIRECTION OUTPUT ;
    USE SIGNAL ;
    PORT
      LAYER M4 ;
        RECT  17.088 27.456 17.28 27.48 ;
    END
  END o[248]
  PIN o[249]
    DIRECTION OUTPUT ;
    USE SIGNAL ;
    PORT
      LAYER M4 ;
        RECT  17.088 27.552 17.28 27.576 ;
    END
  END o[249]
  PIN o[24]
    DIRECTION OUTPUT ;
    USE SIGNAL ;
    PORT
      LAYER M4 ;
        RECT  17.088 4.656 17.28 4.68 ;
    END
  END o[24]
  PIN o[250]
    DIRECTION OUTPUT ;
    USE SIGNAL ;
    PORT
      LAYER M4 ;
        RECT  17.088 27.648 17.28 27.672 ;
    END
  END o[250]
  PIN o[251]
    DIRECTION OUTPUT ;
    USE SIGNAL ;
    PORT
      LAYER M4 ;
        RECT  17.088 27.744 17.28 27.768 ;
    END
  END o[251]
  PIN o[252]
    DIRECTION OUTPUT ;
    USE SIGNAL ;
    PORT
      LAYER M4 ;
        RECT  17.088 27.84 17.28 27.864 ;
    END
  END o[252]
  PIN o[253]
    DIRECTION OUTPUT ;
    USE SIGNAL ;
    PORT
      LAYER M4 ;
        RECT  17.088 27.984 17.28 28.008 ;
    END
  END o[253]
  PIN o[254]
    DIRECTION OUTPUT ;
    USE SIGNAL ;
    PORT
      LAYER M4 ;
        RECT  17.088 28.08 17.28 28.104 ;
    END
  END o[254]
  PIN o[255]
    DIRECTION OUTPUT ;
    USE SIGNAL ;
    PORT
      LAYER M4 ;
        RECT  17.088 28.176 17.28 28.2 ;
    END
  END o[255]
  PIN o[256]
    DIRECTION OUTPUT ;
    USE SIGNAL ;
    PORT
      LAYER M4 ;
        RECT  17.088 28.272 17.28 28.296 ;
    END
  END o[256]
  PIN o[257]
    DIRECTION OUTPUT ;
    USE SIGNAL ;
    PORT
      LAYER M4 ;
        RECT  17.088 28.368 17.28 28.392 ;
    END
  END o[257]
  PIN o[258]
    DIRECTION OUTPUT ;
    USE SIGNAL ;
    PORT
      LAYER M4 ;
        RECT  17.088 28.464 17.28 28.488 ;
    END
  END o[258]
  PIN o[259]
    DIRECTION OUTPUT ;
    USE SIGNAL ;
    PORT
      LAYER M4 ;
        RECT  17.088 28.56 17.28 28.584 ;
    END
  END o[259]
  PIN o[25]
    DIRECTION OUTPUT ;
    USE SIGNAL ;
    PORT
      LAYER M4 ;
        RECT  17.088 4.752 17.28 4.776 ;
    END
  END o[25]
  PIN o[260]
    DIRECTION OUTPUT ;
    USE SIGNAL ;
    PORT
      LAYER M4 ;
        RECT  17.088 28.656 17.28 28.68 ;
    END
  END o[260]
  PIN o[261]
    DIRECTION OUTPUT ;
    USE SIGNAL ;
    PORT
      LAYER M4 ;
        RECT  17.088 28.8 17.28 28.824 ;
    END
  END o[261]
  PIN o[262]
    DIRECTION OUTPUT ;
    USE SIGNAL ;
    PORT
      LAYER M4 ;
        RECT  17.088 28.896 17.28 28.92 ;
    END
  END o[262]
  PIN o[263]
    DIRECTION OUTPUT ;
    USE SIGNAL ;
    PORT
      LAYER M4 ;
        RECT  17.088 28.992 17.28 29.016 ;
    END
  END o[263]
  PIN o[264]
    DIRECTION OUTPUT ;
    USE SIGNAL ;
    PORT
      LAYER M4 ;
        RECT  17.088 29.088 17.28 29.112 ;
    END
  END o[264]
  PIN o[265]
    DIRECTION OUTPUT ;
    USE SIGNAL ;
    PORT
      LAYER M4 ;
        RECT  17.088 29.184 17.28 29.208 ;
    END
  END o[265]
  PIN o[266]
    DIRECTION OUTPUT ;
    USE SIGNAL ;
    PORT
      LAYER M4 ;
        RECT  17.088 29.28 17.28 29.304 ;
    END
  END o[266]
  PIN o[267]
    DIRECTION OUTPUT ;
    USE SIGNAL ;
    PORT
      LAYER M4 ;
        RECT  17.088 29.376 17.28 29.4 ;
    END
  END o[267]
  PIN o[268]
    DIRECTION OUTPUT ;
    USE SIGNAL ;
    PORT
      LAYER M4 ;
        RECT  17.088 29.472 17.28 29.496 ;
    END
  END o[268]
  PIN o[269]
    DIRECTION OUTPUT ;
    USE SIGNAL ;
    PORT
      LAYER M4 ;
        RECT  17.088 29.568 17.28 29.592 ;
    END
  END o[269]
  PIN o[26]
    DIRECTION OUTPUT ;
    USE SIGNAL ;
    PORT
      LAYER M4 ;
        RECT  17.088 4.848 17.28 4.872 ;
    END
  END o[26]
  PIN o[270]
    DIRECTION OUTPUT ;
    USE SIGNAL ;
    PORT
      LAYER M4 ;
        RECT  17.088 29.712 17.28 29.736 ;
    END
  END o[270]
  PIN o[271]
    DIRECTION OUTPUT ;
    USE SIGNAL ;
    PORT
      LAYER M4 ;
        RECT  17.088 29.808 17.28 29.832 ;
    END
  END o[271]
  PIN o[272]
    DIRECTION OUTPUT ;
    USE SIGNAL ;
    PORT
      LAYER M4 ;
        RECT  17.088 29.904 17.28 29.928 ;
    END
  END o[272]
  PIN o[273]
    DIRECTION OUTPUT ;
    USE SIGNAL ;
    PORT
      LAYER M4 ;
        RECT  17.088 30 17.28 30.024 ;
    END
  END o[273]
  PIN o[274]
    DIRECTION OUTPUT ;
    USE SIGNAL ;
    PORT
      LAYER M4 ;
        RECT  17.088 30.096 17.28 30.12 ;
    END
  END o[274]
  PIN o[275]
    DIRECTION OUTPUT ;
    USE SIGNAL ;
    PORT
      LAYER M4 ;
        RECT  17.088 30.192 17.28 30.216 ;
    END
  END o[275]
  PIN o[27]
    DIRECTION OUTPUT ;
    USE SIGNAL ;
    PORT
      LAYER M4 ;
        RECT  17.088 4.992 17.28 5.016 ;
    END
  END o[27]
  PIN o[28]
    DIRECTION OUTPUT ;
    USE SIGNAL ;
    PORT
      LAYER M4 ;
        RECT  17.088 5.088 17.28 5.112 ;
    END
  END o[28]
  PIN o[29]
    DIRECTION OUTPUT ;
    USE SIGNAL ;
    PORT
      LAYER M4 ;
        RECT  17.088 5.184 17.28 5.208 ;
    END
  END o[29]
  PIN o[2]
    DIRECTION OUTPUT ;
    USE SIGNAL ;
    PORT
      LAYER M4 ;
        RECT  17.088 2.448 17.28 2.472 ;
    END
  END o[2]
  PIN o[30]
    DIRECTION OUTPUT ;
    USE SIGNAL ;
    PORT
      LAYER M4 ;
        RECT  17.088 5.28 17.28 5.304 ;
    END
  END o[30]
  PIN o[31]
    DIRECTION OUTPUT ;
    USE SIGNAL ;
    PORT
      LAYER M4 ;
        RECT  17.088 5.376 17.28 5.4 ;
    END
  END o[31]
  PIN o[32]
    DIRECTION OUTPUT ;
    USE SIGNAL ;
    PORT
      LAYER M4 ;
        RECT  17.088 5.472 17.28 5.496 ;
    END
  END o[32]
  PIN o[33]
    DIRECTION OUTPUT ;
    USE SIGNAL ;
    PORT
      LAYER M4 ;
        RECT  17.088 5.568 17.28 5.592 ;
    END
  END o[33]
  PIN o[34]
    DIRECTION OUTPUT ;
    USE SIGNAL ;
    PORT
      LAYER M4 ;
        RECT  17.088 5.664 17.28 5.688 ;
    END
  END o[34]
  PIN o[35]
    DIRECTION OUTPUT ;
    USE SIGNAL ;
    PORT
      LAYER M4 ;
        RECT  17.088 5.76 17.28 5.784 ;
    END
  END o[35]
  PIN o[36]
    DIRECTION OUTPUT ;
    USE SIGNAL ;
    PORT
      LAYER M4 ;
        RECT  17.088 5.904 17.28 5.928 ;
    END
  END o[36]
  PIN o[37]
    DIRECTION OUTPUT ;
    USE SIGNAL ;
    PORT
      LAYER M4 ;
        RECT  17.088 6 17.28 6.024 ;
    END
  END o[37]
  PIN o[38]
    DIRECTION OUTPUT ;
    USE SIGNAL ;
    PORT
      LAYER M4 ;
        RECT  17.088 6.096 17.28 6.12 ;
    END
  END o[38]
  PIN o[39]
    DIRECTION OUTPUT ;
    USE SIGNAL ;
    PORT
      LAYER M4 ;
        RECT  17.088 6.192 17.28 6.216 ;
    END
  END o[39]
  PIN o[3]
    DIRECTION OUTPUT ;
    USE SIGNAL ;
    PORT
      LAYER M4 ;
        RECT  17.088 2.544 17.28 2.568 ;
    END
  END o[3]
  PIN o[40]
    DIRECTION OUTPUT ;
    USE SIGNAL ;
    PORT
      LAYER M4 ;
        RECT  17.088 6.288 17.28 6.312 ;
    END
  END o[40]
  PIN o[41]
    DIRECTION OUTPUT ;
    USE SIGNAL ;
    PORT
      LAYER M4 ;
        RECT  17.088 6.384 17.28 6.408 ;
    END
  END o[41]
  PIN o[42]
    DIRECTION OUTPUT ;
    USE SIGNAL ;
    PORT
      LAYER M4 ;
        RECT  17.088 6.48 17.28 6.504 ;
    END
  END o[42]
  PIN o[43]
    DIRECTION OUTPUT ;
    USE SIGNAL ;
    PORT
      LAYER M4 ;
        RECT  17.088 6.576 17.28 6.6 ;
    END
  END o[43]
  PIN o[44]
    DIRECTION OUTPUT ;
    USE SIGNAL ;
    PORT
      LAYER M4 ;
        RECT  17.088 6.72 17.28 6.744 ;
    END
  END o[44]
  PIN o[45]
    DIRECTION OUTPUT ;
    USE SIGNAL ;
    PORT
      LAYER M4 ;
        RECT  17.088 6.816 17.28 6.84 ;
    END
  END o[45]
  PIN o[46]
    DIRECTION OUTPUT ;
    USE SIGNAL ;
    PORT
      LAYER M4 ;
        RECT  17.088 6.912 17.28 6.936 ;
    END
  END o[46]
  PIN o[47]
    DIRECTION OUTPUT ;
    USE SIGNAL ;
    PORT
      LAYER M4 ;
        RECT  17.088 7.008 17.28 7.032 ;
    END
  END o[47]
  PIN o[48]
    DIRECTION OUTPUT ;
    USE SIGNAL ;
    PORT
      LAYER M4 ;
        RECT  17.088 7.104 17.28 7.128 ;
    END
  END o[48]
  PIN o[49]
    DIRECTION OUTPUT ;
    USE SIGNAL ;
    PORT
      LAYER M4 ;
        RECT  17.088 7.2 17.28 7.224 ;
    END
  END o[49]
  PIN o[4]
    DIRECTION OUTPUT ;
    USE SIGNAL ;
    PORT
      LAYER M4 ;
        RECT  17.088 2.64 17.28 2.664 ;
    END
  END o[4]
  PIN o[50]
    DIRECTION OUTPUT ;
    USE SIGNAL ;
    PORT
      LAYER M4 ;
        RECT  17.088 7.296 17.28 7.32 ;
    END
  END o[50]
  PIN o[51]
    DIRECTION OUTPUT ;
    USE SIGNAL ;
    PORT
      LAYER M4 ;
        RECT  17.088 7.392 17.28 7.416 ;
    END
  END o[51]
  PIN o[52]
    DIRECTION OUTPUT ;
    USE SIGNAL ;
    PORT
      LAYER M4 ;
        RECT  17.088 7.536 17.28 7.56 ;
    END
  END o[52]
  PIN o[53]
    DIRECTION OUTPUT ;
    USE SIGNAL ;
    PORT
      LAYER M4 ;
        RECT  17.088 7.632 17.28 7.656 ;
    END
  END o[53]
  PIN o[54]
    DIRECTION OUTPUT ;
    USE SIGNAL ;
    PORT
      LAYER M4 ;
        RECT  17.088 7.728 17.28 7.752 ;
    END
  END o[54]
  PIN o[55]
    DIRECTION OUTPUT ;
    USE SIGNAL ;
    PORT
      LAYER M4 ;
        RECT  17.088 7.824 17.28 7.848 ;
    END
  END o[55]
  PIN o[56]
    DIRECTION OUTPUT ;
    USE SIGNAL ;
    PORT
      LAYER M4 ;
        RECT  17.088 7.92 17.28 7.944 ;
    END
  END o[56]
  PIN o[57]
    DIRECTION OUTPUT ;
    USE SIGNAL ;
    PORT
      LAYER M4 ;
        RECT  17.088 8.016 17.28 8.04 ;
    END
  END o[57]
  PIN o[58]
    DIRECTION OUTPUT ;
    USE SIGNAL ;
    PORT
      LAYER M4 ;
        RECT  17.088 8.112 17.28 8.136 ;
    END
  END o[58]
  PIN o[59]
    DIRECTION OUTPUT ;
    USE SIGNAL ;
    PORT
      LAYER M4 ;
        RECT  17.088 8.208 17.28 8.232 ;
    END
  END o[59]
  PIN o[5]
    DIRECTION OUTPUT ;
    USE SIGNAL ;
    PORT
      LAYER M4 ;
        RECT  17.088 2.736 17.28 2.76 ;
    END
  END o[5]
  PIN o[60]
    DIRECTION OUTPUT ;
    USE SIGNAL ;
    PORT
      LAYER M4 ;
        RECT  17.088 8.304 17.28 8.328 ;
    END
  END o[60]
  PIN o[61]
    DIRECTION OUTPUT ;
    USE SIGNAL ;
    PORT
      LAYER M4 ;
        RECT  17.088 8.448 17.28 8.472 ;
    END
  END o[61]
  PIN o[62]
    DIRECTION OUTPUT ;
    USE SIGNAL ;
    PORT
      LAYER M4 ;
        RECT  17.088 8.544 17.28 8.568 ;
    END
  END o[62]
  PIN o[63]
    DIRECTION OUTPUT ;
    USE SIGNAL ;
    PORT
      LAYER M4 ;
        RECT  17.088 8.64 17.28 8.664 ;
    END
  END o[63]
  PIN o[64]
    DIRECTION OUTPUT ;
    USE SIGNAL ;
    PORT
      LAYER M4 ;
        RECT  17.088 8.736 17.28 8.76 ;
    END
  END o[64]
  PIN o[65]
    DIRECTION OUTPUT ;
    USE SIGNAL ;
    PORT
      LAYER M4 ;
        RECT  17.088 8.832 17.28 8.856 ;
    END
  END o[65]
  PIN o[66]
    DIRECTION OUTPUT ;
    USE SIGNAL ;
    PORT
      LAYER M4 ;
        RECT  17.088 8.928 17.28 8.952 ;
    END
  END o[66]
  PIN o[67]
    DIRECTION OUTPUT ;
    USE SIGNAL ;
    PORT
      LAYER M4 ;
        RECT  17.088 9.024 17.28 9.048 ;
    END
  END o[67]
  PIN o[68]
    DIRECTION OUTPUT ;
    USE SIGNAL ;
    PORT
      LAYER M4 ;
        RECT  17.088 9.12 17.28 9.144 ;
    END
  END o[68]
  PIN o[69]
    DIRECTION OUTPUT ;
    USE SIGNAL ;
    PORT
      LAYER M4 ;
        RECT  17.088 9.264 17.28 9.288 ;
    END
  END o[69]
  PIN o[6]
    DIRECTION OUTPUT ;
    USE SIGNAL ;
    PORT
      LAYER M4 ;
        RECT  17.088 2.832 17.28 2.856 ;
    END
  END o[6]
  PIN o[70]
    DIRECTION OUTPUT ;
    USE SIGNAL ;
    PORT
      LAYER M4 ;
        RECT  17.088 9.36 17.28 9.384 ;
    END
  END o[70]
  PIN o[71]
    DIRECTION OUTPUT ;
    USE SIGNAL ;
    PORT
      LAYER M4 ;
        RECT  17.088 9.456 17.28 9.48 ;
    END
  END o[71]
  PIN o[72]
    DIRECTION OUTPUT ;
    USE SIGNAL ;
    PORT
      LAYER M4 ;
        RECT  17.088 9.552 17.28 9.576 ;
    END
  END o[72]
  PIN o[73]
    DIRECTION OUTPUT ;
    USE SIGNAL ;
    PORT
      LAYER M4 ;
        RECT  17.088 9.648 17.28 9.672 ;
    END
  END o[73]
  PIN o[74]
    DIRECTION OUTPUT ;
    USE SIGNAL ;
    PORT
      LAYER M4 ;
        RECT  17.088 9.744 17.28 9.768 ;
    END
  END o[74]
  PIN o[75]
    DIRECTION OUTPUT ;
    USE SIGNAL ;
    PORT
      LAYER M4 ;
        RECT  17.088 9.84 17.28 9.864 ;
    END
  END o[75]
  PIN o[76]
    DIRECTION OUTPUT ;
    USE SIGNAL ;
    PORT
      LAYER M4 ;
        RECT  17.088 9.936 17.28 9.96 ;
    END
  END o[76]
  PIN o[77]
    DIRECTION OUTPUT ;
    USE SIGNAL ;
    PORT
      LAYER M4 ;
        RECT  17.088 10.08 17.28 10.104 ;
    END
  END o[77]
  PIN o[78]
    DIRECTION OUTPUT ;
    USE SIGNAL ;
    PORT
      LAYER M4 ;
        RECT  17.088 10.176 17.28 10.2 ;
    END
  END o[78]
  PIN o[79]
    DIRECTION OUTPUT ;
    USE SIGNAL ;
    PORT
      LAYER M4 ;
        RECT  17.088 10.272 17.28 10.296 ;
    END
  END o[79]
  PIN o[7]
    DIRECTION OUTPUT ;
    USE SIGNAL ;
    PORT
      LAYER M4 ;
        RECT  17.088 2.928 17.28 2.952 ;
    END
  END o[7]
  PIN o[80]
    DIRECTION OUTPUT ;
    USE SIGNAL ;
    PORT
      LAYER M4 ;
        RECT  17.088 10.368 17.28 10.392 ;
    END
  END o[80]
  PIN o[81]
    DIRECTION OUTPUT ;
    USE SIGNAL ;
    PORT
      LAYER M4 ;
        RECT  17.088 10.464 17.28 10.488 ;
    END
  END o[81]
  PIN o[82]
    DIRECTION OUTPUT ;
    USE SIGNAL ;
    PORT
      LAYER M4 ;
        RECT  17.088 10.56 17.28 10.584 ;
    END
  END o[82]
  PIN o[83]
    DIRECTION OUTPUT ;
    USE SIGNAL ;
    PORT
      LAYER M4 ;
        RECT  17.088 10.656 17.28 10.68 ;
    END
  END o[83]
  PIN o[84]
    DIRECTION OUTPUT ;
    USE SIGNAL ;
    PORT
      LAYER M4 ;
        RECT  17.088 10.752 17.28 10.776 ;
    END
  END o[84]
  PIN o[85]
    DIRECTION OUTPUT ;
    USE SIGNAL ;
    PORT
      LAYER M4 ;
        RECT  17.088 10.848 17.28 10.872 ;
    END
  END o[85]
  PIN o[86]
    DIRECTION OUTPUT ;
    USE SIGNAL ;
    PORT
      LAYER M4 ;
        RECT  17.088 10.992 17.28 11.016 ;
    END
  END o[86]
  PIN o[87]
    DIRECTION OUTPUT ;
    USE SIGNAL ;
    PORT
      LAYER M4 ;
        RECT  17.088 11.088 17.28 11.112 ;
    END
  END o[87]
  PIN o[88]
    DIRECTION OUTPUT ;
    USE SIGNAL ;
    PORT
      LAYER M4 ;
        RECT  17.088 11.184 17.28 11.208 ;
    END
  END o[88]
  PIN o[89]
    DIRECTION OUTPUT ;
    USE SIGNAL ;
    PORT
      LAYER M4 ;
        RECT  17.088 11.28 17.28 11.304 ;
    END
  END o[89]
  PIN o[8]
    DIRECTION OUTPUT ;
    USE SIGNAL ;
    PORT
      LAYER M4 ;
        RECT  17.088 3.024 17.28 3.048 ;
    END
  END o[8]
  PIN o[90]
    DIRECTION OUTPUT ;
    USE SIGNAL ;
    PORT
      LAYER M4 ;
        RECT  17.088 11.376 17.28 11.4 ;
    END
  END o[90]
  PIN o[91]
    DIRECTION OUTPUT ;
    USE SIGNAL ;
    PORT
      LAYER M4 ;
        RECT  17.088 11.472 17.28 11.496 ;
    END
  END o[91]
  PIN o[92]
    DIRECTION OUTPUT ;
    USE SIGNAL ;
    PORT
      LAYER M4 ;
        RECT  17.088 11.568 17.28 11.592 ;
    END
  END o[92]
  PIN o[93]
    DIRECTION OUTPUT ;
    USE SIGNAL ;
    PORT
      LAYER M4 ;
        RECT  17.088 11.664 17.28 11.688 ;
    END
  END o[93]
  PIN o[94]
    DIRECTION OUTPUT ;
    USE SIGNAL ;
    PORT
      LAYER M4 ;
        RECT  17.088 11.808 17.28 11.832 ;
    END
  END o[94]
  PIN o[95]
    DIRECTION OUTPUT ;
    USE SIGNAL ;
    PORT
      LAYER M4 ;
        RECT  17.088 11.904 17.28 11.928 ;
    END
  END o[95]
  PIN o[96]
    DIRECTION OUTPUT ;
    USE SIGNAL ;
    PORT
      LAYER M4 ;
        RECT  17.088 12 17.28 12.024 ;
    END
  END o[96]
  PIN o[97]
    DIRECTION OUTPUT ;
    USE SIGNAL ;
    PORT
      LAYER M4 ;
        RECT  17.088 12.096 17.28 12.12 ;
    END
  END o[97]
  PIN o[98]
    DIRECTION OUTPUT ;
    USE SIGNAL ;
    PORT
      LAYER M4 ;
        RECT  17.088 12.192 17.28 12.216 ;
    END
  END o[98]
  PIN o[99]
    DIRECTION OUTPUT ;
    USE SIGNAL ;
    PORT
      LAYER M4 ;
        RECT  17.088 12.288 17.28 12.312 ;
    END
  END o[99]
  PIN o[9]
    DIRECTION OUTPUT ;
    USE SIGNAL ;
    PORT
      LAYER M4 ;
        RECT  17.088 3.12 17.28 3.144 ;
    END
  END o[9]
  PIN rs
    DIRECTION INPUT ;
    USE SIGNAL ;
    PORT
      LAYER M5 ;
        RECT  11.856 32.208 11.88 32.4 ;
    END
  END rs
  PIN VDD
    DIRECTION INOUT ;
    USE POWER ;
    PORT
      LAYER M5 ;
        RECT  13.392 2.151 13.512 30.249 ;
        RECT  10.692 2.151 10.812 30.249 ;
        RECT  7.992 2.151 8.112 30.249 ;
        RECT  5.292 2.151 5.412 30.249 ;
        RECT  2.592 2.151 2.712 30.249 ;
    END
  END VDD
  PIN VSS
    DIRECTION INOUT ;
    USE GROUND ;
    PORT
      LAYER M5 ;
        RECT  13.2 2.137 13.32 30.263 ;
        RECT  10.5 2.137 10.62 30.263 ;
        RECT  7.8 2.137 7.92 30.263 ;
        RECT  5.1 2.137 5.22 30.263 ;
        RECT  2.4 2.137 2.52 30.263 ;
    END
  END VSS
  OBS
    LAYER RVTN ;
     RECT  2.16 2.16 15.12 2.295 ;
     RECT  2.16 2.565 15.12 2.835 ;
     RECT  2.16 3.105 15.12 3.375 ;
     RECT  2.16 3.645 15.12 3.915 ;
     RECT  2.16 4.185 15.12 4.455 ;
     RECT  2.16 4.725 15.12 4.995 ;
     RECT  2.16 5.265 15.12 5.535 ;
     RECT  2.16 5.805 15.12 6.075 ;
     RECT  2.16 6.345 15.12 6.615 ;
     RECT  2.16 6.885 15.12 7.155 ;
     RECT  2.16 7.425 15.12 7.695 ;
     RECT  2.16 7.965 15.12 8.235 ;
     RECT  2.16 8.505 15.12 8.775 ;
     RECT  2.16 9.045 15.12 9.315 ;
     RECT  2.16 9.585 15.12 9.855 ;
     RECT  2.16 10.125 15.12 10.395 ;
     RECT  2.16 10.665 15.12 10.935 ;
     RECT  2.16 11.205 15.12 11.475 ;
     RECT  2.16 11.745 15.12 12.015 ;
     RECT  2.16 12.285 15.12 12.555 ;
     RECT  2.16 12.825 15.12 13.095 ;
     RECT  2.16 13.365 15.12 13.635 ;
     RECT  2.16 13.905 15.12 14.175 ;
     RECT  2.16 14.445 15.12 14.715 ;
     RECT  2.16 14.985 15.12 15.255 ;
     RECT  2.16 15.525 15.12 15.795 ;
     RECT  2.16 16.065 15.12 16.335 ;
     RECT  2.16 16.605 15.12 16.875 ;
     RECT  2.16 17.145 15.12 17.415 ;
     RECT  2.16 17.685 15.12 17.955 ;
     RECT  2.16 18.225 15.12 18.495 ;
     RECT  2.16 18.765 15.12 19.035 ;
     RECT  2.16 19.305 15.12 19.575 ;
     RECT  2.16 19.845 15.12 20.115 ;
     RECT  2.16 20.385 15.12 20.655 ;
     RECT  2.16 20.925 15.12 21.195 ;
     RECT  2.16 21.465 15.12 21.735 ;
     RECT  2.16 22.005 15.12 22.275 ;
     RECT  2.16 22.545 15.12 22.815 ;
     RECT  2.16 23.085 15.12 23.355 ;
     RECT  2.16 23.625 15.12 23.895 ;
     RECT  2.16 24.165 15.12 24.435 ;
     RECT  2.16 24.705 15.12 24.975 ;
     RECT  2.16 25.245 15.12 25.515 ;
     RECT  2.16 25.785 15.12 26.055 ;
     RECT  2.16 26.325 15.12 26.595 ;
     RECT  2.16 26.865 15.12 27.135 ;
     RECT  2.16 27.405 15.12 27.675 ;
     RECT  2.16 27.945 15.12 28.215 ;
     RECT  2.16 28.485 15.12 28.755 ;
     RECT  2.16 29.025 15.12 29.295 ;
     RECT  2.16 29.565 15.12 29.835 ;
     RECT  2.16 30.105 15.12 30.24 ;
    LAYER RVTP ;
     RECT  2.16 2.295 15.12 2.565 ;
     RECT  2.16 2.835 15.12 3.105 ;
     RECT  2.16 3.375 15.12 3.645 ;
     RECT  2.16 3.915 15.12 4.185 ;
     RECT  2.16 4.455 15.12 4.725 ;
     RECT  2.16 4.995 15.12 5.265 ;
     RECT  2.16 5.535 15.12 5.805 ;
     RECT  2.16 6.075 15.12 6.345 ;
     RECT  2.16 6.615 15.12 6.885 ;
     RECT  2.16 7.155 15.12 7.425 ;
     RECT  2.16 7.695 15.12 7.965 ;
     RECT  2.16 8.235 15.12 8.505 ;
     RECT  2.16 8.775 15.12 9.045 ;
     RECT  2.16 9.315 15.12 9.585 ;
     RECT  2.16 9.855 15.12 10.125 ;
     RECT  2.16 10.395 15.12 10.665 ;
     RECT  2.16 10.935 15.12 11.205 ;
     RECT  2.16 11.475 15.12 11.745 ;
     RECT  2.16 12.015 15.12 12.285 ;
     RECT  2.16 12.555 15.12 12.825 ;
     RECT  2.16 13.095 15.12 13.365 ;
     RECT  2.16 13.635 15.12 13.905 ;
     RECT  2.16 14.175 15.12 14.445 ;
     RECT  2.16 14.715 15.12 14.985 ;
     RECT  2.16 15.255 15.12 15.525 ;
     RECT  2.16 15.795 15.12 16.065 ;
     RECT  2.16 16.335 15.12 16.605 ;
     RECT  2.16 16.875 15.12 17.145 ;
     RECT  2.16 17.415 15.12 17.685 ;
     RECT  2.16 17.955 15.12 18.225 ;
     RECT  2.16 18.495 15.12 18.765 ;
     RECT  2.16 19.035 15.12 19.305 ;
     RECT  2.16 19.575 15.12 19.845 ;
     RECT  2.16 20.115 15.12 20.385 ;
     RECT  2.16 20.655 15.12 20.925 ;
     RECT  2.16 21.195 15.12 21.465 ;
     RECT  2.16 21.735 15.12 22.005 ;
     RECT  2.16 22.275 15.12 22.545 ;
     RECT  2.16 22.815 15.12 23.085 ;
     RECT  2.16 23.355 15.12 23.625 ;
     RECT  2.16 23.895 15.12 24.165 ;
     RECT  2.16 24.435 15.12 24.705 ;
     RECT  2.16 24.975 15.12 25.245 ;
     RECT  2.16 25.515 15.12 25.785 ;
     RECT  2.16 26.055 15.12 26.325 ;
     RECT  2.16 26.595 15.12 26.865 ;
     RECT  2.16 27.135 15.12 27.405 ;
     RECT  2.16 27.675 15.12 27.945 ;
     RECT  2.16 28.215 15.12 28.485 ;
     RECT  2.16 28.755 15.12 29.025 ;
     RECT  2.16 29.295 15.12 29.565 ;
     RECT  2.16 29.835 15.12 30.105 ;
    LAYER M1 ;
     RECT  2.16 2.151 15.12 30.249 ;
    LAYER M2 ;
     RECT  0.211 15.192 0.311 15.21 ;
     RECT  0.211 24.246 0.311 24.264 ;
     RECT  0.211 25.218 0.311 25.236 ;
     RECT  0.391 8.514 0.491 8.532 ;
     RECT  0.247 1.881 0.535 1.899 ;
     RECT  0.535 18.774 0.571 18.792 ;
     RECT  0.571 18.738 0.671 18.792 ;
     RECT  0.535 1.881 2.16 2.016 ;
     RECT  0.211 10.944 2.16 10.962 ;
     RECT  0.535 11.952 2.16 11.97 ;
     RECT  0.211 13.032 2.16 13.05 ;
     RECT  0.211 16.344 2.16 16.362 ;
     RECT  0.671 18.774 2.16 18.792 ;
     RECT  0.535 27.342 2.16 27.36 ;
     RECT  0.211 30.276 2.16 30.294 ;
     RECT  2.16 1.881 4.171 30.294 ;
     RECT  4.171 1.881 4.495 30.33 ;
     RECT  4.495 1.881 7.375 30.402 ;
     RECT  7.375 1.836 9.527 30.402 ;
     RECT  9.527 1.881 11.327 30.402 ;
     RECT  11.327 1.926 11.759 30.402 ;
     RECT  11.759 1.926 12.587 30.366 ;
     RECT  12.587 1.926 12.983 30.33 ;
     RECT  12.983 1.926 13.703 30.249 ;
     RECT  13.703 2.106 14.279 30.249 ;
     RECT  14.279 2.151 15.12 30.249 ;
     RECT  15.12 2.196 15.431 30.06 ;
     RECT  15.431 2.196 16.007 16.524 ;
     RECT  15.431 17.352 16.007 22.23 ;
     RECT  15.431 23.022 16.007 30.06 ;
     RECT  16.007 24.876 16.043 26.514 ;
     RECT  16.007 4.23 16.511 16.524 ;
     RECT  16.007 17.352 16.511 17.91 ;
     RECT  16.043 24.876 16.511 24.894 ;
     RECT  16.043 25.686 16.511 26.154 ;
     RECT  16.007 27.306 16.511 28.404 ;
     RECT  16.007 29.268 16.511 30.06 ;
     RECT  16.007 2.466 16.547 3.474 ;
     RECT  16.511 4.23 16.547 7.956 ;
     RECT  16.511 8.784 16.547 12.312 ;
     RECT  16.511 13.068 16.547 16.164 ;
     RECT  16.511 17.352 16.547 17.514 ;
     RECT  16.007 18.846 16.547 22.23 ;
     RECT  16.007 23.67 16.547 23.814 ;
     RECT  16.511 26.136 16.547 26.154 ;
     RECT  16.511 27.306 16.547 27.864 ;
     RECT  16.511 29.502 16.547 30.06 ;
     RECT  16.547 4.806 16.583 5.454 ;
     RECT  16.547 7.434 16.583 7.452 ;
     RECT  16.547 9.9 16.583 10.152 ;
     RECT  16.547 10.98 16.583 11.304 ;
     RECT  16.547 13.536 16.583 13.626 ;
     RECT  16.547 15.336 16.583 15.354 ;
     RECT  16.547 19.386 16.583 19.674 ;
     RECT  16.547 20.97 16.583 22.23 ;
     RECT  16.547 23.796 16.583 23.814 ;
     RECT  16.583 13.608 16.619 13.626 ;
     RECT  16.583 19.386 16.619 19.404 ;
     RECT  16.583 21.276 16.619 22.23 ;
     RECT  16.547 27.306 16.619 27.324 ;
     RECT  16.619 22.212 17.087 22.23 ;
    LAYER M3 ;
     RECT  7.38 1.831 7.398 1.957 ;
     RECT  11.304 1.876 11.322 1.957 ;
     RECT  0.252 1.876 0.27 1.993 ;
     RECT  9.504 1.831 9.522 1.993 ;
     RECT  6.768 1.957 7.398 2.029 ;
     RECT  0.252 1.993 0.558 2.059 ;
     RECT  4.536 1.921 4.554 2.065 ;
     RECT  11.304 1.957 11.61 2.101 ;
     RECT  12.564 2.065 12.582 2.101 ;
     RECT  13.68 1.921 13.698 2.101 ;
     RECT  3.06 2.059 3.078 2.143 ;
     RECT  4.5 2.065 4.554 2.143 ;
     RECT  6.3 2.029 7.398 2.143 ;
     RECT  8.496 2.101 8.514 2.143 ;
     RECT  11.304 2.101 12.87 2.143 ;
     RECT  13.68 2.101 14.274 2.143 ;
     RECT  0.216 2.059 0.558 2.237 ;
     RECT  6.3 2.143 8.514 2.251 ;
     RECT  0.252 2.237 0.558 2.333 ;
     RECT  4.5 2.143 5.205 2.371 ;
     RECT  4.32 2.371 5.205 2.413 ;
     RECT  6.3 2.251 8.586 2.443 ;
     RECT  9.36 1.993 9.522 2.443 ;
     RECT  15.984 2.191 16.002 2.461 ;
     RECT  0.288 2.333 0.558 2.477 ;
     RECT  10.515 2.143 14.274 2.489 ;
     RECT  4.32 2.413 5.397 2.497 ;
     RECT  6.3 2.443 9.522 2.497 ;
     RECT  15.984 2.461 16.542 2.525 ;
     RECT  2.415 2.143 3.078 2.533 ;
     RECT  4.32 2.497 9.594 2.533 ;
     RECT  4.176 2.533 9.594 2.569 ;
     RECT  10.515 2.489 11.394 2.569 ;
     RECT  2.415 2.533 3.258 2.635 ;
     RECT  12.132 2.489 14.274 2.635 ;
     RECT  15.444 2.533 15.462 2.635 ;
     RECT  4.176 2.569 11.394 2.759 ;
     RECT  2.304 2.635 3.258 2.779 ;
     RECT  4.176 2.759 9.666 2.779 ;
     RECT  0.288 2.477 0.414 2.861 ;
     RECT  12.132 2.635 15.462 2.861 ;
     RECT  12.132 2.861 15.426 3.029 ;
     RECT  12.132 3.029 13.95 3.053 ;
     RECT  14.724 3.029 15.426 3.209 ;
     RECT  2.304 2.779 9.666 3.541 ;
     RECT  10.515 2.759 11.394 3.541 ;
     RECT  12.168 3.053 13.95 3.569 ;
     RECT  14.832 3.209 15.426 3.643 ;
     RECT  16.524 2.525 16.542 3.643 ;
     RECT  2.304 3.541 11.394 3.811 ;
     RECT  2.304 3.811 11.79 4.217 ;
     RECT  12.564 3.569 13.95 4.225 ;
     RECT  14.832 3.643 16.542 4.225 ;
     RECT  2.304 4.217 10.818 4.252 ;
     RECT  12.564 4.225 16.542 4.301 ;
     RECT  11.772 4.217 11.79 4.411 ;
     RECT  12.564 4.301 15.426 4.411 ;
     RECT  2.268 4.252 10.818 4.415 ;
     RECT  2.304 4.415 10.818 4.541 ;
     RECT  16.524 4.301 16.542 4.651 ;
     RECT  11.772 4.411 15.426 4.757 ;
     RECT  11.772 4.757 14.094 4.829 ;
     RECT  14.832 4.757 15.426 4.919 ;
     RECT  2.304 4.541 9.45 4.955 ;
     RECT  10.515 4.541 10.818 4.987 ;
     RECT  11.772 4.829 13.554 4.987 ;
     RECT  16.524 4.651 16.578 5.083 ;
     RECT  10.515 4.987 13.554 5.189 ;
     RECT  10.515 5.189 10.89 5.333 ;
     RECT  2.304 4.955 9.234 5.371 ;
     RECT  2.232 5.371 9.234 5.495 ;
     RECT  15.984 5.083 16.578 5.501 ;
     RECT  14.832 4.919 14.85 5.659 ;
     RECT  15.984 5.501 16.542 5.659 ;
     RECT  2.304 5.495 9.234 5.701 ;
     RECT  10.515 5.333 10.854 5.701 ;
     RECT  14.832 5.659 16.542 5.701 ;
     RECT  11.7 5.189 13.554 5.737 ;
     RECT  14.364 5.701 16.542 5.737 ;
     RECT  2.304 5.701 10.854 6.079 ;
     RECT  11.7 5.737 16.542 6.079 ;
     RECT  2.304 6.079 16.542 6.269 ;
     RECT  0.252 4.699 0.27 6.331 ;
     RECT  0.252 6.331 0.342 6.379 ;
     RECT  0.252 6.379 0.414 6.413 ;
     RECT  0.324 6.413 0.414 6.509 ;
     RECT  3.96 6.269 16.542 6.575 ;
     RECT  10.515 6.575 16.542 6.809 ;
     RECT  3.996 6.575 9.558 6.845 ;
     RECT  11.952 6.809 16.542 6.881 ;
     RECT  12.168 6.881 16.542 7.223 ;
     RECT  0.324 6.509 0.342 7.229 ;
     RECT  12.168 7.223 12.186 7.349 ;
     RECT  12.96 7.223 16.542 7.42 ;
     RECT  5.115 6.845 9.558 7.501 ;
     RECT  10.515 6.809 10.926 7.501 ;
     RECT  3.996 6.845 4.302 7.591 ;
     RECT  5.115 7.501 10.926 7.627 ;
     RECT  12.96 7.42 16.578 7.661 ;
     RECT  2.304 6.269 3.222 7.735 ;
     RECT  3.996 7.591 4.338 7.735 ;
     RECT  5.115 7.627 11.43 7.771 ;
     RECT  5.115 7.771 11.97 7.889 ;
     RECT  0.252 7.675 0.27 7.963 ;
     RECT  2.304 7.735 4.338 7.963 ;
     RECT  5.115 7.889 10.854 7.963 ;
     RECT  0.252 7.963 0.342 8.045 ;
     RECT  11.808 7.889 11.826 8.069 ;
     RECT  0.324 8.045 0.342 8.141 ;
     RECT  2.304 7.963 10.854 8.195 ;
     RECT  12.96 7.661 16.542 8.251 ;
     RECT  3.996 8.195 10.854 8.501 ;
     RECT  0.396 8.491 0.486 8.537 ;
     RECT  0.396 8.537 0.414 8.573 ;
     RECT  6.264 8.501 10.854 8.731 ;
     RECT  3.996 8.501 5.397 8.765 ;
     RECT  6.264 8.731 11.43 8.771 ;
     RECT  12.888 8.251 16.542 8.779 ;
     RECT  12.528 8.779 16.542 8.861 ;
     RECT  12.528 8.861 15.426 8.879 ;
     RECT  16.488 8.861 16.542 8.969 ;
     RECT  12.528 8.879 13.914 9.121 ;
     RECT  5.115 8.765 5.397 9.247 ;
     RECT  5.115 9.247 5.49 9.319 ;
     RECT  6.264 8.771 10.854 9.319 ;
     RECT  14.724 8.879 15.426 9.389 ;
     RECT  3.996 8.765 4.194 9.517 ;
     RECT  5.115 9.319 10.854 9.547 ;
     RECT  5.004 9.547 10.854 9.553 ;
     RECT  3.96 9.517 4.194 9.595 ;
     RECT  5.004 9.553 10.926 9.595 ;
     RECT  16.524 8.969 16.542 9.739 ;
     RECT  12.24 9.121 13.914 9.751 ;
     RECT  14.724 9.389 14.886 9.751 ;
     RECT  16.488 9.739 16.542 9.835 ;
     RECT  12.24 9.751 14.886 9.931 ;
     RECT  16.488 9.835 16.578 10.021 ;
     RECT  2.304 8.195 3.222 10.123 ;
     RECT  3.96 9.595 10.926 10.123 ;
     RECT  12.132 9.931 14.886 10.123 ;
     RECT  2.304 10.123 14.886 10.163 ;
     RECT  15.984 10.021 16.578 10.205 ;
     RECT  4.032 10.163 14.886 10.229 ;
     RECT  11.916 10.229 14.886 10.291 ;
     RECT  11.916 10.291 15.426 10.427 ;
     RECT  0.252 9.739 0.27 10.589 ;
     RECT  2.304 10.163 3.222 10.732 ;
     RECT  12.42 10.427 15.426 10.769 ;
     RECT  2.268 10.732 3.222 10.895 ;
     RECT  12.42 10.769 14.598 10.931 ;
     RECT  0.216 10.843 0.234 10.967 ;
     RECT  2.304 10.895 3.222 11.011 ;
     RECT  4.032 10.229 10.797 11.011 ;
     RECT  4.032 11.011 10.854 11.131 ;
     RECT  15.408 10.769 15.426 11.137 ;
     RECT  15.408 11.137 15.462 11.173 ;
     RECT  16.524 10.205 16.578 11.173 ;
     RECT  2.304 11.011 3.258 11.275 ;
     RECT  4.032 11.131 11.43 11.275 ;
     RECT  2.304 11.275 11.43 11.309 ;
     RECT  15.408 11.173 16.578 11.309 ;
     RECT  12.672 10.931 14.598 11.551 ;
     RECT  15.408 11.309 16.542 11.551 ;
     RECT  12.672 11.551 16.542 11.749 ;
     RECT  12.132 11.749 16.542 11.939 ;
     RECT  0.252 11.419 0.27 11.947 ;
     RECT  0.252 11.947 0.558 12.029 ;
     RECT  12.24 11.939 16.542 12.029 ;
     RECT  0.252 12.029 0.342 12.221 ;
     RECT  15.984 12.029 16.542 12.323 ;
     RECT  2.304 11.309 10.818 12.331 ;
     RECT  1.728 12.331 10.818 12.389 ;
     RECT  10.515 12.389 10.818 12.475 ;
     RECT  1.728 12.389 9.774 12.653 ;
     RECT  15.984 12.323 16.506 12.653 ;
     RECT  10.515 12.475 11.43 12.721 ;
     RECT  12.24 12.029 14.886 12.721 ;
     RECT  10.515 12.721 14.886 12.811 ;
     RECT  10.515 12.811 15.462 12.929 ;
     RECT  0.252 12.221 0.27 12.941 ;
     RECT  0.216 13.027 0.234 13.133 ;
     RECT  2.304 12.653 9.774 13.163 ;
     RECT  11.628 12.929 15.462 13.361 ;
     RECT  16.524 13.063 16.542 13.531 ;
     RECT  16.524 13.531 16.578 13.603 ;
     RECT  11.628 13.361 14.922 13.661 ;
     RECT  10.515 12.929 10.797 13.711 ;
     RECT  16.524 13.603 16.614 13.819 ;
     RECT  16.488 13.819 16.614 14.045 ;
     RECT  2.304 13.163 9.63 14.107 ;
     RECT  10.368 13.711 10.797 14.107 ;
     RECT  2.304 14.107 10.797 14.171 ;
     RECT  16.488 14.045 16.542 14.203 ;
     RECT  11.988 13.661 14.922 14.443 ;
     RECT  15.984 14.203 16.542 14.443 ;
     RECT  2.304 14.171 6.57 14.819 ;
     RECT  11.988 14.443 16.542 14.819 ;
     RECT  7.308 14.171 10.797 14.881 ;
     RECT  0.252 14.395 0.27 14.923 ;
     RECT  0.216 14.923 0.27 14.971 ;
     RECT  3.96 14.819 6.57 15.061 ;
     RECT  7.308 14.881 10.962 15.061 ;
     RECT  12.168 14.819 16.542 15.115 ;
     RECT  0.216 14.971 0.306 15.215 ;
     RECT  12.168 15.115 16.578 15.359 ;
     RECT  0.252 15.215 0.27 15.389 ;
     RECT  12.168 15.359 16.542 15.389 ;
     RECT  3.96 15.061 10.962 15.485 ;
     RECT  3.996 15.485 10.962 15.529 ;
     RECT  3.996 15.529 11.43 15.739 ;
     RECT  12.168 15.389 15.426 15.739 ;
     RECT  3.996 15.739 15.426 15.827 ;
     RECT  2.304 14.819 3.222 16.033 ;
     RECT  3.996 15.827 12.006 16.169 ;
     RECT  0.216 16.267 0.234 16.367 ;
     RECT  2.304 16.033 3.258 16.375 ;
     RECT  3.996 16.169 10.797 16.375 ;
     RECT  12.852 15.827 15.426 16.375 ;
     RECT  16.488 15.389 16.542 16.375 ;
     RECT  12.852 16.375 16.542 16.397 ;
     RECT  12.852 16.397 16.506 16.529 ;
     RECT  12.852 16.529 16.002 16.589 ;
     RECT  11.628 16.169 12.006 16.645 ;
     RECT  12.852 16.589 15.426 16.645 ;
     RECT  11.628 16.645 15.426 16.979 ;
     RECT  0.252 16.843 0.27 17.131 ;
     RECT  2.304 16.375 10.797 17.419 ;
     RECT  16.524 17.275 16.542 17.467 ;
     RECT  0.252 17.131 0.342 17.501 ;
     RECT  2.304 17.419 11.394 17.501 ;
     RECT  16.488 17.467 16.542 17.597 ;
     RECT  12.384 16.979 15.426 17.653 ;
     RECT  16.488 17.597 16.506 17.653 ;
     RECT  2.304 17.501 11.358 17.681 ;
     RECT  12.384 17.653 16.506 17.693 ;
     RECT  12.384 17.693 14.85 17.761 ;
     RECT  2.304 17.681 10.926 17.789 ;
     RECT  12.132 17.761 14.85 17.879 ;
     RECT  12.276 17.879 14.85 18.149 ;
     RECT  10.515 17.789 10.926 18.221 ;
     RECT  0.252 17.501 0.27 18.317 ;
     RECT  14.832 18.149 14.85 18.463 ;
     RECT  2.304 17.789 3.222 18.571 ;
     RECT  3.96 17.789 9.738 18.571 ;
     RECT  15.984 17.693 16.506 18.619 ;
     RECT  2.304 18.571 9.738 18.661 ;
     RECT  10.515 18.221 10.797 18.661 ;
     RECT  2.304 18.661 10.797 18.701 ;
     RECT  0.54 18.715 0.594 18.733 ;
     RECT  0.54 18.733 0.666 18.797 ;
     RECT  0.54 18.797 0.558 18.845 ;
     RECT  14.832 18.463 14.886 18.907 ;
     RECT  15.984 18.619 16.542 18.907 ;
     RECT  14.832 18.907 16.542 19.003 ;
     RECT  12.276 18.149 14.058 19.111 ;
     RECT  14.796 19.003 16.542 19.139 ;
     RECT  12.24 19.111 14.058 19.301 ;
     RECT  13.032 19.301 14.058 19.381 ;
     RECT  14.796 19.139 15.426 19.381 ;
     RECT  16.524 19.139 16.542 19.381 ;
     RECT  2.304 18.701 9.666 19.507 ;
     RECT  10.515 18.701 10.797 19.507 ;
     RECT  11.952 19.345 12.078 19.565 ;
     RECT  2.304 19.507 10.797 19.615 ;
     RECT  16.524 19.381 16.614 19.661 ;
     RECT  12.06 19.565 12.078 19.805 ;
     RECT  2.304 19.615 10.854 19.877 ;
     RECT  10.26 19.877 10.854 19.949 ;
     RECT  10.26 19.949 10.818 20.183 ;
     RECT  2.304 19.877 9.45 20.309 ;
     RECT  0.252 19.435 0.27 20.347 ;
     RECT  0.252 20.347 0.414 20.381 ;
     RECT  13.032 19.381 15.426 20.389 ;
     RECT  12.564 20.389 15.426 20.429 ;
     RECT  0.288 20.381 0.414 20.635 ;
     RECT  3.996 20.309 9.45 20.875 ;
     RECT  10.26 20.183 10.797 20.875 ;
     RECT  0.288 20.635 0.45 20.909 ;
     RECT  13.215 20.429 15.426 20.923 ;
     RECT  16.524 19.661 16.578 20.923 ;
     RECT  13.215 20.923 16.578 21.019 ;
     RECT  0.288 20.909 0.378 21.053 ;
     RECT  13.215 21.019 16.614 21.235 ;
     RECT  13.176 21.235 16.614 21.361 ;
     RECT  3.996 20.875 10.797 21.397 ;
     RECT  11.844 21.091 11.934 21.397 ;
     RECT  13.068 21.361 16.614 21.403 ;
     RECT  3.996 21.397 11.934 21.497 ;
     RECT  2.304 20.309 3.258 21.499 ;
     RECT  3.996 21.497 10.797 21.499 ;
     RECT  2.304 21.499 10.797 21.569 ;
     RECT  11.592 21.497 11.934 21.691 ;
     RECT  12.924 21.403 16.614 21.691 ;
     RECT  11.592 21.691 16.614 21.839 ;
     RECT  11.592 21.839 16.038 21.929 ;
     RECT  2.304 21.569 3.222 21.973 ;
     RECT  3.96 21.569 10.797 22.301 ;
     RECT  17.064 22.207 17.082 22.301 ;
     RECT  2.268 21.973 3.222 22.315 ;
     RECT  3.96 22.301 9.594 22.315 ;
     RECT  2.268 22.315 9.594 22.343 ;
     RECT  11.88 21.929 16.038 22.397 ;
     RECT  0.252 21.211 0.27 22.541 ;
     RECT  2.268 22.343 9.45 22.685 ;
     RECT  11.88 22.397 16.002 22.739 ;
     RECT  11.88 22.739 12.438 22.747 ;
     RECT  10.332 22.301 10.797 22.843 ;
     RECT  11.808 22.747 12.438 22.843 ;
     RECT  10.332 22.843 12.438 23.153 ;
     RECT  2.304 22.685 9.45 23.287 ;
     RECT  10.332 23.153 12.006 23.287 ;
     RECT  13.215 22.739 16.002 23.521 ;
     RECT  2.304 23.287 12.006 23.585 ;
     RECT  13.068 23.521 16.002 23.665 ;
     RECT  13.068 23.665 16.542 23.791 ;
     RECT  4.032 23.585 12.006 23.927 ;
     RECT  0.288 23.947 0.306 23.995 ;
     RECT  13.068 23.791 16.578 24.029 ;
     RECT  11.916 23.927 12.006 24.061 ;
     RECT  13.068 24.029 16.002 24.061 ;
     RECT  0.216 23.995 0.306 24.284 ;
     RECT  2.304 23.585 3.258 24.395 ;
     RECT  11.916 24.061 16.002 24.467 ;
     RECT  11.916 24.467 12.114 24.701 ;
     RECT  12.096 24.701 12.114 24.773 ;
     RECT  13.215 24.467 16.002 24.811 ;
     RECT  13.215 24.811 16.506 24.899 ;
     RECT  2.415 24.395 3.258 25.051 ;
     RECT  4.032 23.927 10.797 25.051 ;
     RECT  0.252 24.284 0.27 25.195 ;
     RECT  2.415 25.051 10.797 25.205 ;
     RECT  0.216 25.195 0.27 25.213 ;
     RECT  13.215 24.899 16.038 25.213 ;
     RECT  0.216 25.213 0.306 25.241 ;
     RECT  0.252 25.241 0.306 25.277 ;
     RECT  2.415 25.205 3.258 25.435 ;
     RECT  13.032 25.213 16.038 25.619 ;
     RECT  13.032 25.619 15.462 25.819 ;
     RECT  16.488 25.627 16.506 25.819 ;
     RECT  12.672 25.819 15.462 25.979 ;
     RECT  16.488 25.819 16.542 26.159 ;
     RECT  2.304 25.435 3.258 26.257 ;
     RECT  4.14 25.205 10.797 26.257 ;
     RECT  2.304 26.257 10.797 26.347 ;
     RECT  2.304 26.347 11.43 26.393 ;
     RECT  12.78 25.979 15.462 26.491 ;
     RECT  2.304 26.393 10.797 26.969 ;
     RECT  2.304 26.969 3.258 27.019 ;
     RECT  12.78 26.491 16.038 27.031 ;
     RECT  2.268 27.019 3.258 27.095 ;
     RECT  4.032 26.969 10.797 27.115 ;
     RECT  12.564 27.031 16.038 27.301 ;
     RECT  0.252 25.277 0.27 27.337 ;
     RECT  0.252 27.337 0.558 27.355 ;
     RECT  4.032 27.115 11.43 27.485 ;
     RECT  12.564 27.301 16.614 27.485 ;
     RECT  0.252 27.355 0.666 27.581 ;
     RECT  12.564 27.485 16.542 27.599 ;
     RECT  12.564 27.599 14.058 27.671 ;
     RECT  4.068 27.485 11.43 27.841 ;
     RECT  12.564 27.671 13.497 27.913 ;
     RECT  14.832 27.599 16.542 28.013 ;
     RECT  4.068 27.841 11.466 28.111 ;
     RECT  12.276 27.913 13.497 28.111 ;
     RECT  0.252 27.581 0.306 28.253 ;
     RECT  14.832 28.013 16.506 28.301 ;
     RECT  0.288 28.253 0.306 28.363 ;
     RECT  14.832 28.301 15.426 28.381 ;
     RECT  2.304 27.095 3.258 28.459 ;
     RECT  4.068 28.111 13.497 28.459 ;
     RECT  2.304 28.459 13.497 28.481 ;
     RECT  16.488 28.301 16.506 28.493 ;
     RECT  2.304 28.481 9.774 28.651 ;
     RECT  10.515 28.481 13.497 28.651 ;
     RECT  14.508 28.381 15.426 28.651 ;
     RECT  2.268 28.651 9.774 28.733 ;
     RECT  2.268 28.733 9.45 28.787 ;
     RECT  10.515 28.651 15.426 28.787 ;
     RECT  11.556 28.787 15.426 28.823 ;
     RECT  11.592 28.823 15.426 29.065 ;
     RECT  0.288 28.363 0.414 29.131 ;
     RECT  11.592 29.065 16.002 29.213 ;
     RECT  0.288 29.131 0.486 29.261 ;
     RECT  0.288 29.261 0.414 29.309 ;
     RECT  16.488 29.263 16.506 29.309 ;
     RECT  2.304 28.787 9.45 29.363 ;
     RECT  10.515 28.787 10.797 29.371 ;
     RECT  3.96 29.363 9.45 29.461 ;
     RECT  10.332 29.371 10.797 29.461 ;
     RECT  11.592 29.213 15.426 29.633 ;
     RECT  11.736 29.633 15.426 29.831 ;
     RECT  3.96 29.461 10.797 29.867 ;
     RECT  11.736 29.831 13.497 29.987 ;
     RECT  10.515 29.867 10.797 30.001 ;
     RECT  3.96 29.867 9.774 30.029 ;
     RECT  14.22 29.831 15.426 30.029 ;
     RECT  0.216 29.707 0.234 30.043 ;
     RECT  2.304 29.363 3.222 30.065 ;
     RECT  3.96 30.029 5.205 30.065 ;
     RECT  16.524 29.497 16.542 30.065 ;
     RECT  6.408 30.029 9.486 30.077 ;
     RECT  4.14 30.065 5.205 30.101 ;
     RECT  11.736 29.987 13.305 30.101 ;
     RECT  10.515 30.001 10.854 30.109 ;
     RECT  6.516 30.077 6.858 30.125 ;
     RECT  14.22 30.029 14.886 30.125 ;
     RECT  6.516 30.125 6.534 30.137 ;
     RECT  7.668 30.077 9.486 30.173 ;
     RECT  7.815 30.173 9.162 30.209 ;
     RECT  10.515 30.109 10.926 30.209 ;
     RECT  11.736 30.101 11.826 30.209 ;
     RECT  14.22 30.125 14.85 30.209 ;
     RECT  2.304 30.065 2.505 30.221 ;
     RECT  14.832 30.209 14.85 30.221 ;
     RECT  2.415 30.221 2.505 30.257 ;
     RECT  4.176 30.101 5.205 30.257 ;
     RECT  7.815 30.209 7.905 30.257 ;
     RECT  10.515 30.209 10.605 30.257 ;
     RECT  12.564 30.101 13.305 30.257 ;
     RECT  0.216 30.043 0.27 30.299 ;
     RECT  9.144 30.209 9.162 30.299 ;
     RECT  0.252 30.299 0.27 30.317 ;
     RECT  4.176 30.257 4.554 30.335 ;
     RECT  12.564 30.257 12.978 30.335 ;
     RECT  4.5 30.335 4.554 30.371 ;
     RECT  12.564 30.335 12.582 30.371 ;
     RECT  4.5 30.371 4.518 30.407 ;
     RECT  11.736 30.209 11.754 30.407 ;
     RECT  5.4 31.339 5.418 32.268 ;
    LAYER M4 ;
     RECT  0.156 2.208 0.181 30.216 ;
     RECT  0.181 2.208 0.205 30.312 ;
     RECT  0.205 2.064 0.281 30.312 ;
     RECT  0.281 2.064 2.408 30.216 ;
     RECT  2.408 2.064 2.512 30.252 ;
     RECT  2.512 2.064 3.089 30.12 ;
     RECT  3.089 2.736 5.108 30.12 ;
     RECT  5.108 2.148 5.212 30.252 ;
     RECT  5.212 2.418 5.404 30.12 ;
     RECT  5.389 31.344 5.843 31.368 ;
     RECT  5.404 2.736 6.541 30.12 ;
     RECT  6.541 2.688 6.793 30.12 ;
     RECT  6.793 2.544 6.853 30.12 ;
     RECT  6.853 2.496 6.865 30.12 ;
     RECT  6.865 2.352 7.657 30.12 ;
     RECT  7.657 2.352 7.808 30.168 ;
     RECT  7.808 2.148 7.912 30.252 ;
     RECT  7.912 2.256 8.597 30.168 ;
     RECT  8.597 2.448 9.065 30.168 ;
     RECT  9.065 2.496 9.173 30.168 ;
     RECT  9.173 2.544 9.245 30.168 ;
     RECT  9.245 2.592 9.497 30.168 ;
     RECT  9.497 2.592 10.508 30.12 ;
     RECT  10.508 2.148 10.612 30.252 ;
     RECT  10.612 2.418 10.793 30.12 ;
     RECT  10.793 2.418 10.804 29.982 ;
     RECT  10.804 2.832 10.829 28.776 ;
     RECT  10.829 3.024 11.441 28.776 ;
     RECT  11.441 11.664 11.837 28.68 ;
     RECT  11.441 3.024 11.945 6.792 ;
     RECT  11.845 29.664 11.981 29.688 ;
     RECT  11.837 23.28 12.125 28.68 ;
     RECT  11.945 3.024 12.161 3.624 ;
     RECT  12.161 3.408 13.208 3.624 ;
     RECT  11.945 4.8 13.208 6.792 ;
     RECT  11.441 8.256 13.208 10.392 ;
     RECT  11.837 11.664 13.208 22.008 ;
     RECT  12.125 23.28 13.208 28.2 ;
     RECT  13.208 2.148 13.312 30.252 ;
     RECT  13.312 2.418 13.504 29.982 ;
     RECT  13.504 14.64 13.673 14.664 ;
     RECT  13.504 26.112 13.673 27.384 ;
     RECT  13.504 9.6 13.709 10.104 ;
     RECT  13.504 18.768 13.745 18.792 ;
     RECT  13.504 3.6 13.781 3.624 ;
     RECT  13.504 24.912 13.781 24.936 ;
     RECT  13.504 20.304 13.817 20.616 ;
     RECT  13.817 20.592 14.105 20.616 ;
     RECT  13.504 17.088 14.533 17.64 ;
     RECT  13.504 6.624 14.713 6.648 ;
     RECT  13.504 23.616 14.713 23.64 ;
     RECT  14.533 17.088 14.785 18.12 ;
     RECT  13.504 2.448 14.821 2.472 ;
     RECT  14.713 6.624 14.821 6.84 ;
     RECT  14.785 8.208 14.821 8.232 ;
     RECT  13.504 11.952 14.821 11.976 ;
     RECT  14.785 17.088 14.821 19.032 ;
     RECT  13.504 21.84 14.821 22.2 ;
     RECT  14.713 23.472 14.821 23.64 ;
     RECT  13.673 26.64 14.821 27.384 ;
     RECT  14.713 29.904 14.821 29.928 ;
     RECT  14.821 2.448 15.397 20.232 ;
     RECT  14.821 21.264 15.397 30.216 ;
     RECT  15.397 2.448 15.973 30.216 ;
     RECT  15.973 2.208 17.1 30.216 ;
    LAYER M5 ;
     RECT  2.4 2.137 2.52 2.151 ;
     RECT  5.1 2.137 5.22 2.151 ;
     RECT  7.8 2.137 7.92 2.151 ;
     RECT  10.5 2.137 10.62 2.151 ;
     RECT  13.2 2.137 13.32 2.151 ;
     RECT  7.8 2.151 8.112 2.485 ;
     RECT  6.864 2.485 8.112 2.867 ;
     RECT  2.4 2.151 2.712 3.061 ;
     RECT  2.304 3.061 2.712 3.299 ;
     RECT  7.8 2.867 8.112 4.021 ;
     RECT  6.864 4.021 8.112 4.259 ;
     RECT  6.96 4.259 8.112 4.307 ;
     RECT  5.1 2.151 5.412 5.173 ;
     RECT  2.4 3.299 2.712 5.221 ;
     RECT  2.304 5.221 2.712 5.363 ;
     RECT  7.8 4.307 8.112 6.181 ;
     RECT  7.68 6.181 8.112 6.421 ;
     RECT  7.68 6.421 8.232 7.187 ;
     RECT  7.8 7.187 8.232 9.061 ;
     RECT  5.1 5.173 5.544 10.645 ;
     RECT  5.1 10.645 5.592 10.741 ;
     RECT  7.8 9.061 8.328 13.333 ;
     RECT  6.864 13.333 8.328 13.715 ;
     RECT  6.864 13.715 8.112 14.003 ;
     RECT  5.1 10.741 5.688 16.405 ;
     RECT  7.8 14.003 8.112 16.741 ;
     RECT  2.4 5.363 2.712 17.077 ;
     RECT  7.8 16.741 9.096 17.123 ;
     RECT  2.4 17.077 3.432 17.699 ;
     RECT  5.1 16.405 5.832 18.133 ;
     RECT  7.8 17.123 8.112 18.709 ;
     RECT  5.1 18.133 5.928 19.957 ;
     RECT  5.1 19.957 6.408 20.867 ;
     RECT  5.1 20.867 5.928 22.645 ;
     RECT  2.4 17.699 2.712 23.173 ;
     RECT  2.304 23.173 2.712 23.363 ;
     RECT  7.8 18.709 8.328 23.459 ;
     RECT  5.1 22.645 6.792 23.749 ;
     RECT  7.8 23.459 8.112 23.749 ;
     RECT  5.1 23.749 8.112 23.987 ;
     RECT  7.8 23.987 8.112 25.141 ;
     RECT  5.1 23.987 6.792 26.101 ;
     RECT  7.8 25.141 8.232 26.101 ;
     RECT  5.1 26.101 8.232 26.243 ;
     RECT  7.8 26.243 8.232 26.531 ;
     RECT  9.12 26.869 9.144 27.059 ;
     RECT  7.8 26.531 8.112 29.461 ;
     RECT  6.864 29.461 8.112 29.603 ;
     RECT  2.4 23.363 2.712 30.249 ;
     RECT  7.8 29.603 8.112 30.249 ;
     RECT  10.5 2.151 10.812 30.249 ;
     RECT  13.2 2.151 13.512 30.249 ;
     RECT  2.4 30.249 2.52 30.263 ;
     RECT  5.1 26.243 5.832 30.263 ;
     RECT  7.8 30.249 7.92 30.263 ;
     RECT  10.5 30.249 10.62 30.263 ;
     RECT  13.2 30.249 13.32 30.263 ;
     RECT  0.192 29.989 0.216 30.323 ;
     RECT  5.808 30.263 5.832 31.379 ;
     RECT  11.856 29.653 11.88 32.272 ;
  END
END dsfd_dvrly_276_WE
END LIBRARY
